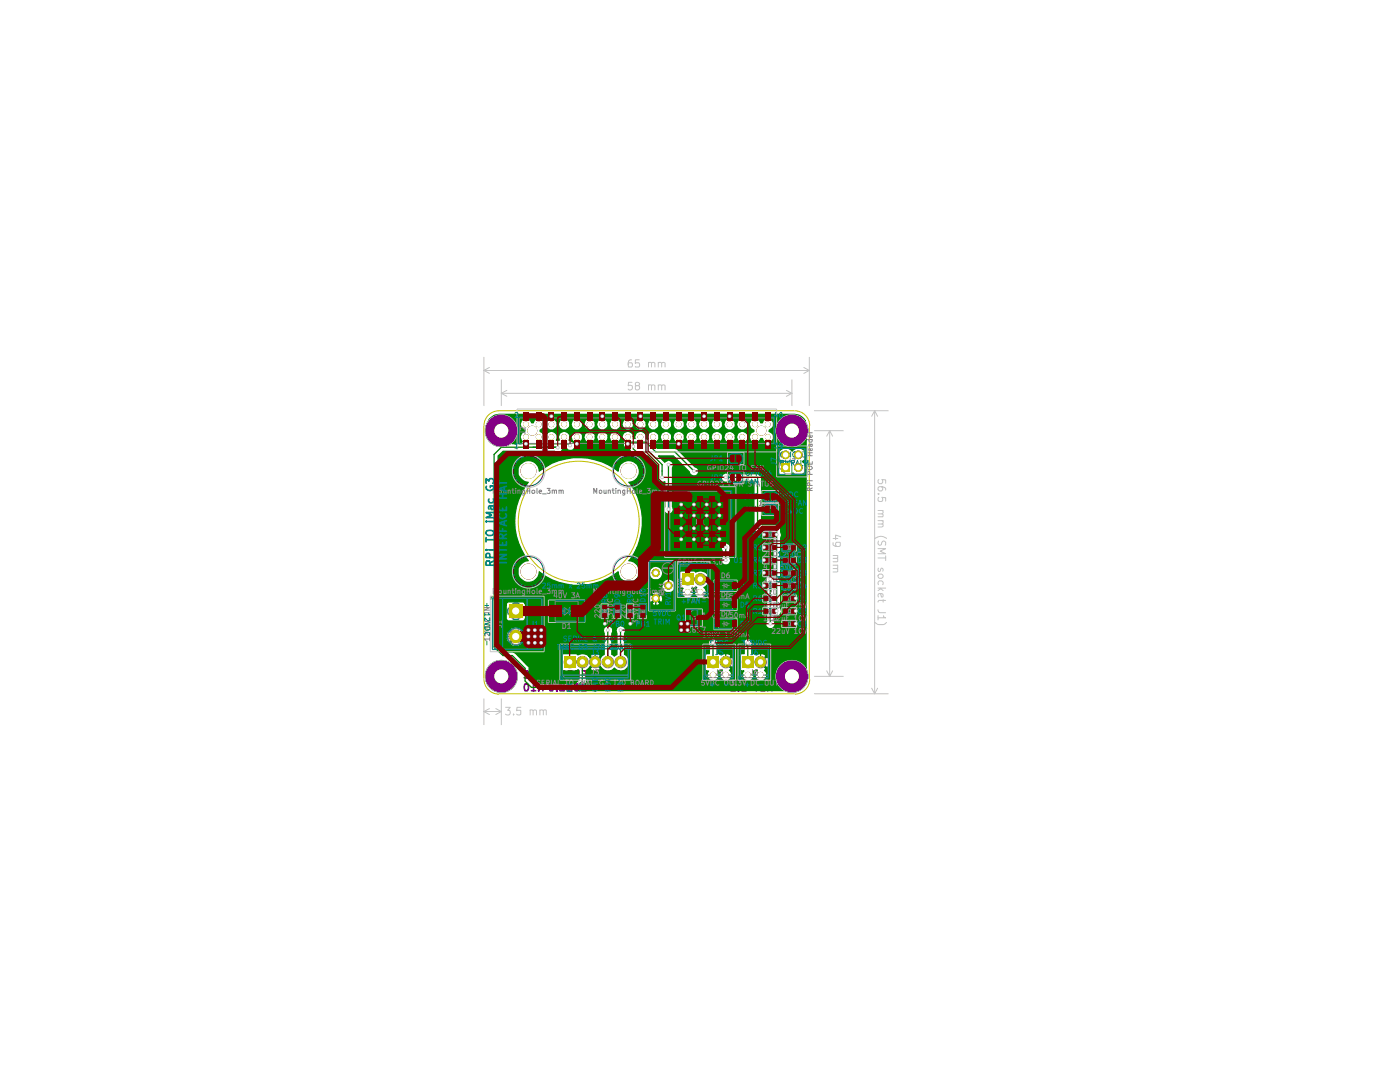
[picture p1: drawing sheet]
<svg xmlns="http://www.w3.org/2000/svg" width="279mm" height="216mm" viewBox="0 0 279 216" stroke-linecap="round" stroke-linejoin="round" font-family="sans-serif">
<g fill="none" stroke="#000084" stroke-width=".2">
<circle cx="100" cy="85.9" r="3.2"/>
<circle cx="100" cy="85.9" r="1.4"/>
<circle cx="158" cy="85.9" r="3.2"/>
<circle cx="158" cy="85.9" r="1.4"/>
<circle cx="100" cy="135" r="3.2"/>
<circle cx="100" cy="135" r="1.4"/>
<circle cx="158" cy="135" r="3.2"/>
<circle cx="158" cy="135" r="1.4"/>
</g>
<g fill="none" stroke="#848484" stroke-width=".2">
<circle cx="100" cy="85.9" r="3.2"/>
<circle cx="158" cy="85.9" r="3.2"/>
<circle cx="100" cy="135" r="3.2"/>
<circle cx="158" cy="135" r="3.2"/>
</g>
<g fill="none" stroke="#840084" stroke-width=".34">
<path d="M104.6 133.9h.6l.4 .6-.1 .5-.3 .3-.6-.1M104.8 136.5l.2-.1a.79 .79 0 0 1 .6 .6 .79 .79 0 0 1-.4 .8h-.4l-.2-.5zM106.1 137.8h.8M106.1 133.9v1.4l1-1.4v1.4M106.9 136.8l-.4-.4v1.4M107.5 137.8h.1M107.8 133.9v1.4M108.3 136.9v.9M108.7 136.3l.3 1.1h-.9M109.6 133.9h.6a1.12 1.12 0 0 1 0 1.4l-.7-.1v-.5h.3M109.8 136.5a.36 .36 0 0 1 .6 .2l.1 .6-.2 .5h-.5l-.2-.5zM111.1 133.9v1.4l.9-1.4v1.4"/>
<path d="M111.1 137.8h.1M112.6 136.5h-.8l-.1 .3 1 1h-1M112.7 133.9v1.4M113.8 134.6l-.5 .7M114 136.5l-.6-.1-.1 .1-.1 .3 .9 1h-.9M114.2 134.6l-.8-.1v-.6h.8v1.4M114.8 136.5l.3-.1a1.1 1.1 0 0 1 .2 1.4h-.4l-.2-.2-.1-.6zM114.9 133.9h.6v1.4h-.6M115 134.5h.5M116.2 133.9h.7v1.4h-.7M116.4 134.5h.5M116.9 136.5l-.6-.1-.2 .1-.1 .3 1 1h-1"/>
<path d="M117.6 133.9v1.4l.9-1.4v1.4M119.2 133.9v1.4M119.9 133.9h.6l.3 .6-.1 .5-.2 .3h-.6v-.6h.2M121.4 133.9v1.4l.8-1.4v1.4M122.9 133.9h.7v1.4h-.7M123.1 134.5h.5M125.9 134.6l-.5 .7M126.3 134.6l-.8-.1-.1-.1v-.5h.9v1.4M146.7 136.5h-.8v.3l.9 1h-.9M147.4 137.8h.1M148.1 137.8h.8M148.9 136.8l-.4-.4v1.4"/>
<path d="M150.4 136.4l.5 1.4 .5-1.4M151.9 136.4h.7v1.4h-.7M152.1 137.1h.5M153.7 137.2l-.5 .6M154.1 137.2l-.7-.1-.2-.2 .1-.4 .8-.1v1.4"/>
</g>
<g fill="#848400">
<path d="M136.1 114.5h2.2v2.2h-2.2z"/>
<path d="M141.2 131h2.2v2.2h-2.2z"/>
<path d="M155.9 92.5h1.7v1.6h-1.7z"/>
<path d="M156.2 90.2l.6-.3v1.7a.85 .85 0 0 1-.8-.5 .85 .85 0 0 1 .2-.9z"/>
<path d="M156.8 89.9a.85 .85 0 0 1 .8 .9 .85 .85 0 0 1-.8 .8z"/>
<path d="M158.7 92.7l.6-.2v1.7a.85 .85 0 0 1-.8-.6 .85 .85 0 0 1 .2-.9z"/>
<path d="M159.3 92.5a.85 .85 0 0 1 .9 .8 .85 .85 0 0 1-.9 .9z"/>
<path d="M158.7 90.2l.6-.3v1.7a.85 .85 0 0 1-.8-.5 .85 .85 0 0 1 .2-.9z"/>
<path d="M159.3 89.9a.85 .85 0 0 1 .9 .9 .85 .85 0 0 1-.9 .8z"/>
<path d="M101.6 120.6h2.6v2.7h-2.6z"/>
<path d="M112.6 131h2.2v2.2h-2.2z"/>
<path d="M148.1 131h2.2v2.2h-2.2z"/>
<circle cx="137.2" cy="118.1" r=".55"/>
<circle cx="133.4" cy="116.8" r=".8"/>
<circle cx="130.9" cy="119.4" r=".8"/>
<circle cx="116.2" cy="132.1" r="1.14"/>
<circle cx="118.8" cy="132.1" r="1.14"/>
<circle cx="121.3" cy="132.1" r="1.14"/>
<circle cx="123.8" cy="132.1" r="1.14"/>
<circle cx="139.8" cy="115.6" r="1.14"/>
<circle cx="139.8" cy="118.1" r=".55"/>
<circle cx="151.9" cy="85.9" r=".97"/>
<circle cx="148.1" cy="87.2" r=".55"/>
<circle cx="148.1" cy="84.7" r=".55"/>
<circle cx="150.7" cy="84.7" r=".55"/>
<circle cx="153.2" cy="84.7" r=".55"/>
<circle cx="140.5" cy="87.2" r=".55"/>
<circle cx="143.1" cy="87.2" r=".55"/>
<circle cx="145.6" cy="87.2" r=".55"/>
<circle cx="140.5" cy="84.7" r=".55"/>
<circle cx="143.1" cy="84.7" r=".55"/>
<circle cx="145.6" cy="84.7" r=".55"/>
<circle cx="135.4" cy="87.2" r=".55"/>
<circle cx="138" cy="87.2" r=".55"/>
<circle cx="135.4" cy="84.7" r=".55"/>
<circle cx="138" cy="84.7" r=".55"/>
<circle cx="158" cy="85.9" r="3.2"/>
<circle cx="150.7" cy="87.2" r=".55"/>
<circle cx="153.2" cy="87.2" r=".55"/>
<circle cx="105.5" cy="114" r="1.57"/>
<circle cx="100" cy="135" r="3.2"/>
<circle cx="102.9" cy="127" r="1.31"/>
<circle cx="158" cy="135" r="3.2"/>
<circle cx="142.3" cy="134.6" r=".55"/>
<circle cx="144.8" cy="132.1" r="1.14"/>
<circle cx="144.8" cy="134.6" r=".55"/>
<circle cx="151.8" cy="134.6" r=".55"/>
<circle cx="151.8" cy="132.1" r="1.14"/>
<circle cx="149.2" cy="134.6" r=".55"/>
<circle cx="125.4" cy="114" r="1.57"/>
<circle cx="125.4" cy="94" r="1.57"/>
<circle cx="105.5" cy="94" r="1.57"/>
<circle cx="125.3" cy="87.2" r=".55"/>
<circle cx="127.8" cy="87.2" r=".55"/>
<circle cx="130.4" cy="87.2" r=".55"/>
<circle cx="132.9" cy="87.2" r=".55"/>
<circle cx="130.9" cy="114.3" r=".8"/>
<circle cx="100" cy="85.9" r="3.2"/>
<circle cx="106.2" cy="85.9" r=".97"/>
<circle cx="105" cy="87.2" r=".55"/>
<circle cx="107.5" cy="87.2" r=".55"/>
<circle cx="110" cy="87.2" r=".55"/>
<circle cx="105" cy="84.7" r=".55"/>
<circle cx="107.5" cy="84.7" r=".55"/>
<circle cx="110" cy="84.7" r=".55"/>
<circle cx="117.7" cy="87.2" r=".55"/>
<circle cx="120.2" cy="87.2" r=".55"/>
<circle cx="122.7" cy="87.2" r=".55"/>
<circle cx="117.7" cy="84.7" r=".55"/>
<circle cx="120.2" cy="84.7" r=".55"/>
<circle cx="112.6" cy="87.2" r=".55"/>
<circle cx="115.1" cy="87.2" r=".55"/>
<circle cx="112.6" cy="84.7" r=".55"/>
<circle cx="115.1" cy="84.7" r=".55"/>
<circle cx="122.7" cy="84.7" r=".55"/>
<circle cx="125.3" cy="84.7" r=".55"/>
<circle cx="127.8" cy="84.7" r=".55"/>
<circle cx="130.4" cy="84.7" r=".55"/>
<circle cx="132.9" cy="84.7" r=".55"/>
</g>
<g fill="none" stroke="#008400" stroke-width=".25">
<path d="M100 89.2l-1.4 1.5v38.4M101.7 90.2l-1.3 1.2v35l.6 .6h1.9M120.2 83.1l34.4-.1v5.6h-19.2l.5 .3 4.1 4.1v7.7M129.6 90.2l1.3 1.2M130.9 90.2h3.8M144.8 95.2h6.4v10.2h3.8v16.5M130.9 119.4v5.1M135.9 102.9h7.7M135.9 105.4h7.7M138.5 100.7v6.9M141 100.7v6.9M143.6 107.6v-6.9h-7.7v6.9h16.2l.4 .3"/>
<path d="M144.8 109.2v2.6M152.5 106.7v20.3M153.7 115.6v8.9M158.8 119.4v7.6h-26.7M137.2 125.7v1.3M142.3 128.3v3.8M144.8 127v5.1M149.2 128.3v3.8M151.8 127v5.1"/>
</g>
<path d="M97.6 83.7a2.84 2.84 0 0 1 2-1l59.4 .1a2.28 2.28 0 0 1 1.7 1.3 3.2 3.2 0 0 0-4.8-.5 3.2 3.2 0 0 0 .2 4.9 3.2 3.2 0 0 0 4.8-.9v45.8l-.3-.4a3.2 3.2 0 0 0-5-.1 3.2 3.2 0 0 0 .9 4.9h-41l1.5-1.5v-2.6l.5-.3h.3a.99 .99 0 0 0 1.1 .5l.8-.3 .1-.2-1-1-1 1h-.3l1.1-1.3h.4l1.6 1.6a1.67 1.67 0 0 0 2-.4 1.74 1.74 0 0 0 2.4 .1 1.74 1.74 0 0 0 .2-2.4h15.4v2.4l.1 .3 .7 .2-.2 .3a1.22 1.22 0 0 0 .5 1.6 1.24 1.24 0 0 0 1.5-.4 1.24 1.24 0 0 0 .1-1.5l.6-.3 .2 .1a1.21 1.21 0 0 0 .3 2.1 1.21 1.21 0 0 0 1.7-1.2l-.3-.7-.2-.2 .2-.1 .1-.2-1.3-1.2 .4-.1 1.1 1.1a1.3 1.3 0 0 0 0-2.1l-1.1 1h-.4l1.2-1.1h1.8v2.5l.2 .3 .6 .1a1.2 1.2 0 0 0 .1 1.6 1.2 1.2 0 0 0 1.6 0 1.2 1.2 0 0 0 .1-1.6h.4l.3-.3 .2 .1a1.17 1.17 0 0 0-.2 1.7 1.17 1.17 0 0 0 1.7 .1 1.17 1.17 0 0 0 0-1.7l.2-.4-1.1-1.3h.3l1 1.1 .3-.1a1.54 1.54 0 0 0 0-1.8l-.3-.2-1 1h-.3l1.1-1.2v-.2l-.4-.2a1.61 1.61 0 0 0-1.5 .2l-.3-.3h-.6v-1.5l.2-.2v-.6l-.2-.4-.6-.3a1.01 1.01 0 0 0-.9 1.5v1.5h-.6l-.3 .6h-1.8v-.3a1.73 1.73 0 0 0-1.9 0l-.2-.3h-.6l.1-1.6a1.06 1.06 0 0 0-.9-1.4l-.7 .3-.2 .4v.6l.2 .2v1.5h-.6l-.4 .3v.3h-15.4l-.6-.4v-4.2l.2-.3v-.6l-.2-.3-.8-.4-.5 .3-.3 .6 .1 .7v4.2l-.5 .3-.5-.3v-4.2l.2-.3v-.6l-.2-.3-.7-.4a1.01 1.01 0 0 0-.8 1.6v4.2l-.4 .2-1.2 1.3h-.4l-.8-.7-.3-.5h.3l1 1.1 1-1.1-.1-.2-.3-.2a1.24 1.24 0 0 0-1.6 .4l-.4-.1a1.85 1.85 0 0 0-2.1-.1l-.2-.3h-2.7l-.4 .5v2.6l.3 .3 2.7 .1 .3-.3 .2 .1v2l-.8 .7h-8.3l-.8-.7-.1-2.7-2.9-2.8-1.9-.1-1.3-1.3v-.4h2.4l.1 .3 .4 .2a1.44 1.44 0 0 0 1.9-.5l-1.2-1.1-1.2 1.1h-2.4v-1.3h1.6l.3 1 .3 .1 1.2-1.2h.3l1.2 1.2a1.29 1.29 0 0 0 .5-1.6l-.2-.6-.3-.1-1.2 1.1h-.3l-1.2-1.1a.96 .96 0 0 0-.6 1.2h-1.6v-1.4h2.4l1.2 1.2 1.2-1.2-.6-.4-.7-.2-.8 .2-.3 .4h-2.4v-5h1.6v2.9l.3 .2 3.2 .1 .4-.6-.1-2.9h25.3l.3 .4 1.1-.1 .2-.3-.8-.7-.8 .7h-25.4l-.2-.3h-3.1l-.4 .3v.3h-1.6v-1.2h30.2a.49 .49 0 0 0 .4 .7l.7-.8h.4l.7 .8h.3a1.61 1.61 0 0 0 0-1.5h-.3l-.7 .7h-.4l-.7-.7h-.3l-.1 .8h-30.2v-1h30.7l.8 .8 .8-.8a.92 .92 0 0 0-1.5-.2l-.1 .2h-30.7v-14.4h3.3a13 13 0 0 0 2.7 7.8l-.6 .1a2.17 2.17 0 0 0-1.3 2.9 2.17 2.17 0 0 0 3 1.1l.9-.9 .2-1a11.9 11.9 0 0 0 6.8 2.7h17.7v.5a1.38 1.38 0 0 0 2 .8 1.38 1.38 0 0 0 .4-2.1 1.38 1.38 0 0 0-2.2 0l-.2 .8h-16a12.4 12.4 0 0 0 7.3-2.7 2.12 2.12 0 0 0 2 2.1 2.12 2.12 0 0 0 2.2-1.9h2v.5a1.39 1.39 0 0 0 1.4 .9 1.39 1.39 0 0 0 1.3-1.2h3.2v2.4l.2 .3 .6 .2-.1 .2a1.22 1.22 0 0 0 .5 1.7 1.24 1.24 0 0 0 1.5-.4 1.24 1.24 0 0 0 0-1.5l.7-.3 .1 .1-.3 .4a1.22 1.22 0 0 0 .5 1.7 1.24 1.24 0 0 0 1.5-.4 1.24 1.24 0 0 0 0-1.5l-.2-.2a1.73 1.73 0 0 0 .8-2.4 1.73 1.73 0 0 0-2.4-.6l-.3-.3h-2.7l-.3 .3-.1 .3h-3.2v-.2a1.36 1.36 0 0 0-1.4-1.3 1.36 1.36 0 0 0-1.3 1.3h-2v-.5a2.17 2.17 0 0 0-2.1-1.9l1.1-1.5 .6-1.2h16.7v.4l.2 .3v1.4l-.2 .2 .1 .8a.95 .95 0 0 0 1.4 .4 .95 .95 0 0 0 .2-1.4l.1-1.5a1.06 1.06 0 0 0-.9-1.5l-.7 .4-.2 .5h-16.7a12.8 12.8 0 0 0-1.7-13 2.16 2.16 0 0 0 2.2-2.1 2.16 2.16 0 0 0-2.1-2.2 2.16 2.16 0 0 0-2.2 2.1 12.8 12.8 0 0 0-15.8 0 2.16 2.16 0 0 0-1.8-2.1 2.16 2.16 0 0 0-2.4 1.5v1.3l.2 .3 .9 1 .9 .2a13 13 0 0 0-2.7 7.9h-3.3v-13.1l1-1h10.3a.93 .93 0 0 0 1 .3 .93 .93 0 0 0 .6-.9h.7l.6 .5h.5l.6-.4v-.8l-.1-.4-1-.5 .1-.7h.3a1.15 1.15 0 0 0 1.1 1.2 1.15 1.15 0 0 0 1.2-1.2h.2v.2a1.15 1.15 0 0 0 1.3 1.1 1.15 1.15 0 0 0 1-1.3h.3v.2a1.15 1.15 0 0 0 1.2 1.1 1.15 1.15 0 0 0 1-1.3h.3v.2a1.15 1.15 0 0 0 1.3 1.1 1.15 1.15 0 0 0 1-1.3h.2l.2 .7 .3 .3a.9 .9 0 0 0 0 1 .9 .9 0 0 0 1 .4l.2 .6 1 .9h2.5l2.1 2.1v1.7l-.2 .2v.6a1.03 1.03 0 0 0 1.5 .5v5l-.2 .3v.6a.95 .95 0 0 0 1.3 .5 .95 .95 0 0 0 .4-1.4v-5.9h9.7a.9 .9 0 0 0 .5 .9 .9 .9 0 0 0 1 0h5.1v9.7l.4 .4h3.3l.1 8.7-.6-.2-.7 .3-.2 .4v.6l.2 .2-.1 8.8a.95 .95 0 0 0 1.4 .4 .95 .95 0 0 0 .2-1.4l.1-1.2a.91 .91 0 0 0 1.2-.2 .91 .91 0 0 0 0-1.1v-14.2l.2-.4-.2-1.5-.3-.5-.5-.2h-3v-9.5l-.2-.3-.6-.4h-5.9l-.5-.1-.7 .3-.2 .5h-9.7l.1-1.9a1.06 1.06 0 0 0-.9-1.5l-.7 .4-1.3-1.2h3l3.2 3.2v.2a.96 .96 0 0 0 1.6 .4 .96 .96 0 0 0-.4-1.6l-.8-.7h17.3v1.7l.3 .6 2.2 .1 .5-.5a1.5 1.5 0 0 0 2.3-.1 1.5 1.5 0 0 0-.5-2.2 1.49 1.49 0 0 0 .3-2.4 1.49 1.49 0 0 0-2.3 .3 1.49 1.49 0 0 0-2.2-.4 1.49 1.49 0 0 0-.1 2.3l-.4 .3-.1 .3h-17.3l-2.9-2.9-.4-.1h-3.5l-1.2-1.2h.1a1.2 1.2 0 0 0 1.4-1.2h.3v.2a1.15 1.15 0 0 0 1.2 1.1 1.15 1.15 0 0 0 1-1.3h.3v.2a1.15 1.15 0 0 0 1.3 1.1 1.15 1.15 0 0 0 1-1.3h.2v.2a1.15 1.15 0 0 0 1.3 1.1 1.15 1.15 0 0 0 1-1.3h.3v.2a1.15 1.15 0 0 0 1.2 1.1 1.15 1.15 0 0 0 1.1-1.3h.2v.2a1.15 1.15 0 0 0 1.3 1.1 1.15 1.15 0 0 0 1-1.3h.3v.2a1.15 1.15 0 0 0 1.2 1.1 1.15 1.15 0 0 0 1-1.3h.3v.2a1.17 1.17 0 0 0 1.6 1 1.17 1.17 0 0 0 .5-1.8 1.17 1.17 0 0 0-1.9 0l-.2 .6h-.3a1.15 1.15 0 0 0-1.1-1 1.15 1.15 0 0 0-1.1 1h-.3v-.2a1.18 1.18 0 0 0-1.2-.8 1.18 1.18 0 0 0-1.1 1h-.2v-.2a1.18 1.18 0 0 0-1.2-.8 1.18 1.18 0 0 0-1.1 1h-.3v-.2a1.18 1.18 0 0 0-1.2-.8 1.18 1.18 0 0 0-1.1 1h-.2v-.2a1.18 1.18 0 0 0-1.2-.8 1.18 1.18 0 0 0-1.1 1h-.3v-.2a1.18 1.18 0 0 0-1.2-.8 1.18 1.18 0 0 0-1 1h-.3v-.2a1.17 1.17 0 0 0-1.5-.8 1.17 1.17 0 0 0-.7 1.6l-.3-.2v-.6a1.14 1.14 0 0 0-1.4-.8 1.14 1.14 0 0 0-.8 1.4h-.4v-.6a1.18 1.18 0 0 0-1.2-.8 1.18 1.18 0 0 0-1.1 1h-.2v-.2a1.18 1.18 0 0 0-1.2-.8 1.18 1.18 0 0 0-1.1 1h-.3v-.2a1.18 1.18 0 0 0-1.2-.8 1.18 1.18 0 0 0-1 1h-.3v-.2a1.18 1.18 0 0 0-1.2-.8 1.18 1.18 0 0 0-1.1 1h-.2v-.2a1.18 1.18 0 0 0-1.2-.8 1.18 1.18 0 0 0-1.1 1h-.3v-.2a1.17 1.17 0 0 0-1.6-.7 1.17 1.17 0 0 0-.5 1.6h-.6h.1a1.16 1.16 0 0 0-1.1-1.7 1.16 1.16 0 0 0-.9 1.7h-.6h.1a1.18 1.18 0 0 0-.8-1.7v-.3l.8-.6v-.7h.3a1.15 1.15 0 0 0 1.1 1.3 1.15 1.15 0 0 0 1.2-1.3h.2v.3a1.15 1.15 0 0 0 1.3 1 1.15 1.15 0 0 0 1-1.3h.3v.3a1.15 1.15 0 0 0 1.2 1 1.15 1.15 0 0 0 1.1-1.3h.2v.3a1.15 1.15 0 0 0 1.3 1 1.15 1.15 0 0 0 1-1.3h.3v.3a1.15 1.15 0 0 0 1.2 1 1.15 1.15 0 0 0 1-1.3h.3v.3a1.15 1.15 0 0 0 1.3 1 1.15 1.15 0 0 0 1-1.3h.2v.3a1.15 1.15 0 0 0 1.3 1 1.15 1.15 0 0 0 1-1.3h.3v.3a1.15 1.15 0 0 0 1.2 1 1.15 1.15 0 0 0 1.1-1.3h.2v.3a1.15 1.15 0 0 0 1.3 1 1.15 1.15 0 0 0 1-1.3h.3v.3a1.15 1.15 0 0 0 1.2 1 1.15 1.15 0 0 0 1-1.3h.3v.3a1.15 1.15 0 0 0 1.3 1 1.15 1.15 0 0 0 1-1.3h.2v.3a1.15 1.15 0 0 0 1.3 1 1.15 1.15 0 0 0 1-1.3h.3v.3a1.15 1.15 0 0 0 1.2 1 1.15 1.15 0 0 0 1.1-1.3h.2v.3a1.15 1.15 0 0 0 1.3 1 1.15 1.15 0 0 0 1-1.3h.3v.3a1.15 1.15 0 0 0 1.2 1 1.15 1.15 0 0 0 1-1.3h.3v.3a1.15 1.15 0 0 0 1.3 1 1.15 1.15 0 0 0 1-1.3h.2l.3 .9 .7 .4v.3a1.18 1.18 0 0 0-1 1.1 1.18 1.18 0 0 0 .9 1.1 1.37 1.37 0 0 0 1.4-.8h.4l.3 .6a1.17 1.17 0 0 0 1.8-.4 1.17 1.17 0 0 0-.8-1.6l.1-.3a1.15 1.15 0 0 0 .5-1.9 1.15 1.15 0 0 0-1.9 .5h-.4l-.1-.3a1.21 1.21 0 0 0-1.2-.5 1.21 1.21 0 0 0-1 .9h-.2v-.1a1.18 1.18 0 0 0-1.2-.8 1.18 1.18 0 0 0-1.1 .9h-.3v-.1a1.18 1.18 0 0 0-1.2-.8 1.18 1.18 0 0 0-1 .9h-.3v-.1a1.18 1.18 0 0 0-1.2-.8 1.18 1.18 0 0 0-1.1 .9h-.2v-.1a1.18 1.18 0 0 0-1.2-.8 1.18 1.18 0 0 0-1.1 .9h-.3v-.1a1.18 1.18 0 0 0-1.2-.8 1.18 1.18 0 0 0-1.1 .9h-.2v-.1a1.18 1.18 0 0 0-1.2-.8 1.18 1.18 0 0 0-1.1 .9h-.3v-.1a1.18 1.18 0 0 0-1.2-.8 1.18 1.18 0 0 0-1 .9h-.3v-.1a1.18 1.18 0 0 0-1.2-.8 1.18 1.18 0 0 0-1.1 .9h-.2v-.1a1.18 1.18 0 0 0-1.2-.8 1.18 1.18 0 0 0-1.1 .9h-.3v-.1a1.18 1.18 0 0 0-1.2-.8 1.18 1.18 0 0 0-1.1 .9h-.2v-.1a1.18 1.18 0 0 0-1.2-.8 1.18 1.18 0 0 0-1.1 .9h-.3v-.1a1.18 1.18 0 0 0-1.2-.8 1.18 1.18 0 0 0-1 .9h-.3v-.1a1.18 1.18 0 0 0-1.2-.8 1.18 1.18 0 0 0-1.1 .9h-.2v-.1a1.18 1.18 0 0 0-1.2-.8 1.18 1.18 0 0 0-1.1 .9h-.3v-.1a1.18 1.18 0 0 0-1.2-.8 1.18 1.18 0 0 0-1.1 .9h-.2v-.1a1.18 1.18 0 0 0-1.2-.8 1.18 1.18 0 0 0-1.1 .9h-.3v-.1a1.13 1.13 0 0 0-1.1-.9 1.13 1.13 0 0 0-1.1 .9h-.3l-.1-.3a1.16 1.16 0 0 0-1.9-.1 1.16 1.16 0 0 0 .6 1.8v.3a1.14 1.14 0 0 0-.5 2l-.1 .4h-2a3.2 3.2 0 0 0 .2-4.9 3.2 3.2 0 0 0-4.8 .5z" fill="#008400"/>
<g fill="none" stroke="#008400" stroke-width=".25">
<path d="M97.6 83.7a2.84 2.84 0 0 1 2-1l59.4 .1a2.28 2.28 0 0 1 1.7 1.3 3.2 3.2 0 0 0-4.8-.5 3.2 3.2 0 0 0 .2 4.9 3.2 3.2 0 0 0 4.8-.9v45.8l-.3-.4a3.2 3.2 0 0 0-5-.1 3.2 3.2 0 0 0 .9 4.9h-41l1.5-1.5v-2.6l.5-.3h.3a.99 .99 0 0 0 1.1 .5l.8-.3 .1-.2-1-1-1 1h-.3l1.1-1.3h.4l1.6 1.6a1.67 1.67 0 0 0 2-.4 1.74 1.74 0 0 0 2.4 .1 1.74 1.74 0 0 0 .2-2.4h15.4v2.4l.1 .3 .7 .2-.2 .3a1.22 1.22 0 0 0 .5 1.6 1.24 1.24 0 0 0 1.5-.4 1.24 1.24 0 0 0 .1-1.5l.6-.3 .2 .1a1.21 1.21 0 0 0 .3 2.1 1.21 1.21 0 0 0 1.7-1.2l-.3-.7-.2-.2 .2-.1 .1-.2-1.3-1.2 .4-.1 1.1 1.1a1.3 1.3 0 0 0 0-2.1l-1.1 1h-.4l1.2-1.1h1.8v2.5l.2 .3 .6 .1a1.2 1.2 0 0 0 .1 1.6 1.2 1.2 0 0 0 1.6 0 1.2 1.2 0 0 0 .1-1.6h.4l.3-.3 .2 .1a1.17 1.17 0 0 0-.2 1.7 1.17 1.17 0 0 0 1.7 .1 1.17 1.17 0 0 0 0-1.7l.2-.4-1.1-1.3h.3l1 1.1 .3-.1a1.54 1.54 0 0 0 0-1.8l-.3-.2-1 1h-.3l1.1-1.2v-.2l-.4-.2a1.61 1.61 0 0 0-1.5 .2l-.3-.3h-.6v-1.5l.2-.2v-.6l-.2-.4-.6-.3a1.01 1.01 0 0 0-.9 1.5v1.5h-.6l-.3 .6h-1.8v-.3a1.73 1.73 0 0 0-1.9 0l-.2-.3h-.6l.1-1.6a1.06 1.06 0 0 0-.9-1.4l-.7 .3-.2 .4v.6l.2 .2v1.5h-.6l-.4 .3v.3h-15.4l-.6-.4v-4.2l.2-.3v-.6l-.2-.3-.8-.4a.97 .97 0 0 0-.7 1.6v4.2l-.5 .3-.5-.3v-4.2l.2-.3v-.6l-.2-.3-.7-.4a1.01 1.01 0 0 0-.8 1.6v4.2l-.4 .2-1.2 1.3h-.4l-.8-.7-.3-.5h.3l1 1.1 1-1.1-.1-.2-.3-.2a1.24 1.24 0 0 0-1.6 .4l-.4-.1a1.85 1.85 0 0 0-2.1-.1l-.2-.3h-2.7l-.4 .5v2.6l.3 .3 2.7 .1 .3-.3 .2 .1v2l-.8 .7h-8.3l-.8-.7-.1-2.7-2.9-2.8-1.9-.1-1.3-1.3v-.4h2.4l.1 .3 .4 .2a1.44 1.44 0 0 0 1.9-.5l-1.2-1.1-1.2 1.1h-2.4v-1.3h1.6l.3 1 .3 .1 1.2-1.2h.3l1.2 1.2a1.29 1.29 0 0 0 .5-1.6l-.2-.6-.3-.1-1.2 1.1h-.3l-1.2-1.1a.96 .96 0 0 0-.6 1.2h-1.6v-1.4h2.4l1.2 1.2 1.2-1.2-.6-.4-.7-.2-.8 .2-.3 .4h-2.4v-5h1.6v2.9l.3 .2 3.2 .1 .4-.6-.1-2.9h25.3l.3 .4 1.1-.1 .2-.3-.8-.7-.8 .7h-25.4l-.2-.3h-3.1l-.4 .3v.3h-1.6v-1.2h30.2a.49 .49 0 0 0 .4 .7l.7-.8h.4l.7 .8h.3a1.61 1.61 0 0 0 0-1.5h-.3l-.7 .7h-.4l-.7-.7h-.3l-.1 .8h-30.2v-1h30.7l.8 .8 .8-.8a.92 .92 0 0 0-1.5-.2l-.1 .2h-30.7v-14.4h3.3a13 13 0 0 0 2.7 7.8l-.6 .1a2.17 2.17 0 0 0-1.3 2.9 2.17 2.17 0 0 0 3 1.1l.9-.9 .2-1a11.9 11.9 0 0 0 6.8 2.7h17.7v.5a1.38 1.38 0 0 0 2 .8 1.38 1.38 0 0 0 .4-2.1 1.38 1.38 0 0 0-2.2 0l-.2 .8h-16a12.4 12.4 0 0 0 7.3-2.7 2.12 2.12 0 0 0 2 2.1 2.12 2.12 0 0 0 2.2-1.9h2v.5a1.39 1.39 0 0 0 1.4 .9 1.39 1.39 0 0 0 1.3-1.2h3.2v2.4l.2 .3 .6 .2-.1 .2a1.22 1.22 0 0 0 .5 1.7 1.24 1.24 0 0 0 1.5-.4 1.24 1.24 0 0 0 0-1.5l.7-.3 .1 .1-.3 .4a1.22 1.22 0 0 0 .5 1.7 1.24 1.24 0 0 0 1.5-.4 1.24 1.24 0 0 0 0-1.5l-.2-.2a1.73 1.73 0 0 0 .8-2.4 1.73 1.73 0 0 0-2.4-.6l-.3-.3h-2.7l-.3 .3-.1 .3h-3.2v-.2a1.36 1.36 0 0 0-1.4-1.3 1.36 1.36 0 0 0-1.3 1.3h-2v-.5a2.17 2.17 0 0 0-2.1-1.9l1.1-1.5 .6-1.2h16.7v.4l.2 .3v1.4l-.2 .2 .1 .8a.95 .95 0 0 0 1.4 .4 .95 .95 0 0 0 .2-1.4l.1-1.5a1.06 1.06 0 0 0-.9-1.5l-.7 .4-.2 .5h-16.7a12.8 12.8 0 0 0-1.7-13 2.16 2.16 0 0 0 2.2-2.1 2.16 2.16 0 0 0-2.1-2.2 2.16 2.16 0 0 0-2.2 2.1 12.8 12.8 0 0 0-15.8 0 2.16 2.16 0 0 0-1.8-2.1 2.16 2.16 0 0 0-2.4 1.5v1.3l.2 .3 .9 1 .9 .2a13 13 0 0 0-2.7 7.9h-3.3v-13.1l1-1h10.3a.93 .93 0 0 0 1 .3 .93 .93 0 0 0 .6-.9h.7l.6 .5h.5l.6-.4v-.8l-.1-.4-1-.5 .1-.7h.3a1.15 1.15 0 0 0 1.1 1.2 1.15 1.15 0 0 0 1.2-1.2h.2v.2a1.15 1.15 0 0 0 1.3 1.1 1.15 1.15 0 0 0 1-1.3h.3v.2a1.15 1.15 0 0 0 1.2 1.1 1.15 1.15 0 0 0 1-1.3h.3v.2a1.15 1.15 0 0 0 1.3 1.1 1.15 1.15 0 0 0 1-1.3h.2l.2 .7 .3 .3a.9 .9 0 0 0 0 1 .9 .9 0 0 0 1 .4l.2 .6 1 .9h2.5l2.1 2.1v1.7l-.2 .2v.6a1.03 1.03 0 0 0 1.5 .5v5l-.2 .3v.6a.95 .95 0 0 0 1.3 .5 .95 .95 0 0 0 .4-1.4v-5.9h9.7a.9 .9 0 0 0 .5 .9 .9 .9 0 0 0 1 0h5.1v9.7l.4 .4h3.3l.1 8.7-.6-.2-.7 .3-.2 .4v.6l.2 .2-.1 8.8a.95 .95 0 0 0 1.4 .4 .95 .95 0 0 0 .2-1.4l.1-1.2a.91 .91 0 0 0 1.2-.2 .91 .91 0 0 0 0-1.1v-14.2l.2-.4-.2-1.5-.3-.5-.5-.2h-3v-9.5l-.2-.3-.6-.4h-5.9l-.5-.1-.7 .3-.2 .5h-9.7l.1-1.9a1.06 1.06 0 0 0-.9-1.5l-.7 .4-1.3-1.2h3l3.2 3.2v.2a.96 .96 0 0 0 1.6 .4 .96 .96 0 0 0-.4-1.6l-.8-.7h17.3v1.7l.3 .6 2.2 .1 .5-.5a1.5 1.5 0 0 0 2.3-.1 1.5 1.5 0 0 0-.5-2.2 1.49 1.49 0 0 0 .3-2.4 1.49 1.49 0 0 0-2.3 .3 1.49 1.49 0 0 0-2.2-.4 1.49 1.49 0 0 0-.1 2.3l-.4 .3-.1 .3h-17.3l-2.9-2.9-.4-.1h-3.5l-1.2-1.2h.1a1.2 1.2 0 0 0 1.4-1.2h.3v.2a1.15 1.15 0 0 0 1.2 1.1 1.15 1.15 0 0 0 1-1.3h.3v.2a1.15 1.15 0 0 0 1.3 1.1 1.15 1.15 0 0 0 1-1.3h.2v.2a1.15 1.15 0 0 0 1.3 1.1 1.15 1.15 0 0 0 1-1.3h.3v.2a1.15 1.15 0 0 0 1.2 1.1 1.15 1.15 0 0 0 1.1-1.3h.2v.2a1.15 1.15 0 0 0 1.3 1.1 1.15 1.15 0 0 0 1-1.3h.3v.2a1.15 1.15 0 0 0 1.2 1.1 1.15 1.15 0 0 0 1-1.3h.3v.2a1.17 1.17 0 0 0 1.6 1 1.17 1.17 0 0 0 .5-1.8 1.17 1.17 0 0 0-1.9 0l-.2 .6h-.3a1.15 1.15 0 0 0-1.1-1 1.15 1.15 0 0 0-1.1 1h-.3v-.2a1.18 1.18 0 0 0-1.2-.8 1.18 1.18 0 0 0-1.1 1h-.2v-.2a1.18 1.18 0 0 0-1.2-.8 1.18 1.18 0 0 0-1.1 1h-.3v-.2a1.18 1.18 0 0 0-1.2-.8 1.18 1.18 0 0 0-1.1 1h-.2v-.2a1.18 1.18 0 0 0-1.2-.8 1.18 1.18 0 0 0-1.1 1h-.3v-.2a1.18 1.18 0 0 0-1.2-.8 1.18 1.18 0 0 0-1 1h-.3v-.2a1.17 1.17 0 0 0-1.5-.8 1.17 1.17 0 0 0-.7 1.6l-.3-.2v-.6a1.14 1.14 0 0 0-1.4-.8 1.14 1.14 0 0 0-.8 1.4h-.4v-.6a1.18 1.18 0 0 0-1.2-.8 1.18 1.18 0 0 0-1.1 1h-.2v-.2a1.18 1.18 0 0 0-1.2-.8 1.18 1.18 0 0 0-1.1 1h-.3v-.2a1.18 1.18 0 0 0-1.2-.8 1.18 1.18 0 0 0-1 1h-.3v-.2a1.18 1.18 0 0 0-1.2-.8 1.18 1.18 0 0 0-1.1 1h-.2v-.2a1.18 1.18 0 0 0-1.2-.8 1.18 1.18 0 0 0-1.1 1h-.3v-.2a1.17 1.17 0 0 0-1.6-.7 1.17 1.17 0 0 0-.5 1.6h-.6h.1a1.16 1.16 0 0 0-1.1-1.7 1.16 1.16 0 0 0-.9 1.7h-.6h.1a1.18 1.18 0 0 0-.8-1.7v-.3l.8-.6v-.7h.3a1.15 1.15 0 0 0 1.1 1.3 1.15 1.15 0 0 0 1.2-1.3h.2v.3a1.15 1.15 0 0 0 1.3 1 1.15 1.15 0 0 0 1-1.3h.3v.3a1.15 1.15 0 0 0 1.2 1 1.15 1.15 0 0 0 1.1-1.3h.2v.3a1.15 1.15 0 0 0 1.3 1 1.15 1.15 0 0 0 1-1.3h.3v.3a1.15 1.15 0 0 0 1.2 1 1.15 1.15 0 0 0 1-1.3h.3v.3a1.15 1.15 0 0 0 1.3 1 1.15 1.15 0 0 0 1-1.3h.2v.3a1.15 1.15 0 0 0 1.3 1 1.15 1.15 0 0 0 1-1.3h.3v.3a1.15 1.15 0 0 0 1.2 1 1.15 1.15 0 0 0 1.1-1.3h.2v.3a1.15 1.15 0 0 0 1.3 1 1.15 1.15 0 0 0 1-1.3h.3v.3a1.15 1.15 0 0 0 1.2 1 1.15 1.15 0 0 0 1-1.3h.3v.3a1.15 1.15 0 0 0 1.3 1 1.15 1.15 0 0 0 1-1.3h.2v.3a1.15 1.15 0 0 0 1.3 1 1.15 1.15 0 0 0 1-1.3h.3v.3a1.15 1.15 0 0 0 1.2 1 1.15 1.15 0 0 0 1.1-1.3h.2v.3a1.15 1.15 0 0 0 1.3 1 1.15 1.15 0 0 0 1-1.3h.3v.3a1.15 1.15 0 0 0 1.2 1 1.15 1.15 0 0 0 1-1.3h.3v.3a1.15 1.15 0 0 0 1.3 1 1.15 1.15 0 0 0 1-1.3h.2l.3 .9 .7 .4v.3a1.18 1.18 0 0 0-1 1.1 1.18 1.18 0 0 0 .9 1.1 1.37 1.37 0 0 0 1.4-.8h.4l.3 .6a1.17 1.17 0 0 0 1.8-.4 1.17 1.17 0 0 0-.8-1.6l.1-.3a1.15 1.15 0 0 0 .5-1.9 1.15 1.15 0 0 0-1.9 .5h-.4l-.1-.3a1.21 1.21 0 0 0-1.2-.5 1.21 1.21 0 0 0-1 .9h-.2v-.1a1.18 1.18 0 0 0-1.2-.8 1.18 1.18 0 0 0-1.1 .9h-.3v-.1a1.18 1.18 0 0 0-1.2-.8 1.18 1.18 0 0 0-1 .9h-.3v-.1a1.18 1.18 0 0 0-1.2-.8 1.18 1.18 0 0 0-1.1 .9h-.2v-.1a1.18 1.18 0 0 0-1.2-.8 1.18 1.18 0 0 0-1.1 .9h-.3v-.1a1.18 1.18 0 0 0-1.2-.8 1.18 1.18 0 0 0-1.1 .9h-.2v-.1a1.18 1.18 0 0 0-1.2-.8 1.18 1.18 0 0 0-1.1 .9h-.3v-.1a1.18 1.18 0 0 0-1.2-.8 1.18 1.18 0 0 0-1 .9h-.3v-.1a1.18 1.18 0 0 0-1.2-.8 1.18 1.18 0 0 0-1.1 .9h-.2v-.1a1.18 1.18 0 0 0-1.2-.8 1.18 1.18 0 0 0-1.1 .9h-.3v-.1a1.18 1.18 0 0 0-1.2-.8 1.18 1.18 0 0 0-1.1 .9h-.2v-.1a1.18 1.18 0 0 0-1.2-.8 1.18 1.18 0 0 0-1.1 .9h-.3v-.1a1.18 1.18 0 0 0-1.2-.8 1.18 1.18 0 0 0-1 .9h-.3v-.1a1.18 1.18 0 0 0-1.2-.8 1.18 1.18 0 0 0-1.1 .9h-.2v-.1a1.18 1.18 0 0 0-1.2-.8 1.18 1.18 0 0 0-1.1 .9h-.3v-.1a1.18 1.18 0 0 0-1.2-.8 1.18 1.18 0 0 0-1.1 .9h-.2v-.1a1.18 1.18 0 0 0-1.2-.8 1.18 1.18 0 0 0-1.1 .9h-.3v-.1a1.13 1.13 0 0 0-1.1-.9 1.13 1.13 0 0 0-1.1 .9h-.3l-.1-.3a1.16 1.16 0 0 0-1.9-.1 1.16 1.16 0 0 0 .6 1.8v.3a1.14 1.14 0 0 0-.5 2l-.1 .4h-2a3.2 3.2 0 0 0 .2-4.9 3.2 3.2 0 0 0-4.8 .5zM100 89.2l11.3 .1M105 88.6h8.4l.4 .3M110 83.1h10.2M115.2 88.6l-.1 .8-.7 .8h-12.7M125.3 88.5l.2-.3h3.4l2 2M126.4 89.1v.5l.7 .6h2.5M130.9 91.4l1.2 1.3v2.5M133.4 92.7v8.9M134.7 90.2l3.8 3.8M98.6 129.1l1.8 1.7h1.8l2.6 2.5v2.6l1.3 1.3h8.8l1.3-1.3v-3.8M108 127h9.5l2.5-2.5h12.1v2.5"/>
<path d="M108 128.3h9.5l1.3 1.2v2.6M121.3 125.7v6.4M123.8 125.7v6.4"/>
</g>
<path d="M105.5 125.7v2.6h1.2v-1.3h-3.8M108 125.7v2.6" fill="none" stroke="#008400" stroke-width="2"/>
<g fill="none" stroke="#c2c200" stroke-width=".2">
<path d="M96.6 84.9v50.6M99.5 82h59.1M99.6 82a3 3 0 0 0-3 3M158.6 82a3 3 0 0 1 3 3M161.5 84.9v50.6M96.6 135.5a3 3 0 0 0 3 3M99.5 138.4h59.1M161.6 135.5a3 3 0 0 1-3 3"/>
<circle cx="115.5" cy="104.1" r="12.1"/>
</g>
<g fill="none" stroke="#000084" stroke-width=".2">
<circle cx="105.5" cy="94" r="3"/>
<circle cx="125.4" cy="94" r="3"/>
<circle cx="105.5" cy="114" r="3"/>
<circle cx="125.4" cy="114" r="3"/>
</g>
<g fill="none" stroke="#c2c2c2" stroke-width=".2">
<path d="M96.6 71.3v9.6M96.6 73.9h64.9M96.6 73.9l1.1 .6M97.7 73.3l-1.1 .6M100 75.8v5.1M100 78.5h58M100 78.5l1.1 .6M101.1 77.9l-1.1 .6M126 71.8l-.4 .1a1.28 1.28 0 0 0-.2 1.3h.6l.2-.6-.2-.2h-.6v.2M126.1 76.3h-.7v.7h.7v.6l-.2 .2h-.4l-.1-.2M127.1 77l-.3-.2 .1-.4a.48 .48 0 0 1 .7 .2l-.3 .4h-.5v.6a.45 .45 0 0 0 .7 .1 .45 .45 0 0 0-.2-.7M127.6 71.8h-.8v.7l.7-.1 .1 .2-.1 .6h-.7"/>
<path d="M129.4 77l.2-.2 .4 .1v.9M129.4 72.4h.6v.8M129.4 72.3v.9M129.4 76.8v1M130 77l.3-.2 .4 .2v.8M130 72.5l.3-.2 .4 .2v.7M131.4 77l.2-.2 .5 .2v.8M131.4 72.4l.5-.1 .2 .2v.7M131.4 72.3v.9M131.4 76.8v1M132.1 77l.2-.2 .4 .2v.8M132.1 72.5l.2-.2 .4 .2v.7"/>
<path d="M156.9 77.9l1.1 .6M158 75.8v5.1M158 78.5l-1.1 .6M160.4 73.3l1.1 .6M161.5 71.3v9.6M161.5 73.9l-1.1 .6M132.6 97.1h14.3v14.2h-14.3zM145.2 94.1h3.3v2.4h-3.3zM145.2 90.3h3.3v2.4h-3.3zM152 97.9h3.3v2.4h-3.3zM155 89h6.1v6.2h-6.1v-13.6h-51.8v8.6h51.8M162.5 85.9h5.8"/>
<path d="M162.5 82h14.8M165.6 85.9v49.1M165.6 85.9l-.6 1.1M165.6 85.9l.6 1.1M174.6 82v56.4M174.6 82l-.6 1.1M174.6 82l.5 1.1M175.2 98.6h.2M175.4 95.7l-.2 .1v.5l.3 .2h.4l.3-.2v-.5l-.2-.1 .8 .1v.6M175.4 99.2l-.2 .3 .1 .5h.8l.1-.5-.2-.3 .8 .1v.7M175.9 97.1l.3 .3v.3l-.3 .3h-.4l-.3-.3 .1-.5a1.19 1.19 0 0 1 1.5 .3v.3M97.8 119h10.8v11h-10.8z"/>
<path d="M109.4 119.7h7.3v4.5h-7.3zM129.4 111.8h5.4v10.1h-5.4zM135.2 112h6.5v7.2h-6.5zM142.5 115.7h4.6v2.3h-4.6zM142.5 119.5h4.6v2.3h-4.6zM152 100.4h3.3v2.5h-3.3zM152.2 106h3v1.4h-3zM152.2 108.5h3v1.5h-3zM152.2 111.1h3v1.4h-3zM152.2 113.6h3v1.5h-3zM152.2 116.2h3v1.4h-3zM152.2 118.7h3v1.4h-3z"/>
<path d="M156 108.5h3v1.5h-3zM156 111.1h3v1.4h-3zM156 113.6h3v1.5h-3zM156 116.2h3v1.4h-3zM156 118.7h3v1.4h-3zM166.3 108.3v.4a1.1 1.1 0 0 0 1.4 .2l-.1-.7h-.7l-.1 .5 .3 .4M166.3 107.4h.9M166.3 110.8h.9M166.3 112.8h.9M167 111.4l.2 .1v.5l-.9 .1M167 113.5h.2v.5l-.9 .1M167.1 110.8l.1 .5-.9 .1"/>
<path d="M167.1 112.8l.1 .6-.9 .1M167.8 107.1l-1-.3v.9M174.6 107.4a1.84 1.84 0 0 1 2.3 0M175.2 109.5h1.6l-1.1 .5 1.1 .5h-1.6M175.2 101.9h1M175.2 103.9h1M175.2 111.3h1.6M175.2 117.3h1.6M175.3 107.9l-.1 .6 .3 .3 .4-.2a.6 .6 0 0 1 .4-.7l.5 .3-.1 .6M175.3 113.4l-.1 .4 .2 .2h.3l.1-.5 .2-.1a.36 .36 0 0 1 .2 .6M175.3 114.7l.2-.1h.4l.3 .3-.1 .4-.6 .1a.45 .45 0 0 1-.2-.7zM175.3 116.7a.52 .52 0 0 1 .2-.8h.4l.3 .2v.6"/>
<path d="M175.7 117.3l.5 .6M175.7 118.4l.2 .7h.3v-.4l-.2-.3-.7 .1v.6M175.8 117.4l-.6 .5M176 102.5l.2 .2v.4h-1M176 104.6l.2 .1v.4l-1 .1M176.1 101.9h.1a.36 .36 0 0 1-.2 .6h-.8M176.1 103.9l.1 .2v.4l-1 .1M176.2 119.6v.5M176.8 119.8h-1.4l-.2 .3M176.8 110.9v.9M96.6 139.4v5.2M100 139.4v5.2"/>
<path d="M111.7 128.5h14.2v7.2h-14.2zM119.9 120.5h1.5v2.9h-1.5zM122.5 120.5h1.4v2.9h-1.4zM125 120.5h1.5v2.9h-1.5zM127.6 120.5h1.4v2.9h-1.4zM136.8 121.5h3.4v3.5h-3.4zM140.3 128.5h6.5v7.2h-6.5zM142.5 123.4h4.6v2.2h-4.6zM147.3 128.5h6.5v7.2h-6.5zM152.2 121.2h3v1.5h-3zM156 121.2h3v1.5h-3zM156 123.8h3v1.4h-3z"/>
<path d="M162.5 135h5.8M162.5 138.4h14.8M165 133.9l.6 1.1M166.2 133.9l-.6 1.1M174 137.3l.6 1.1M174.6 124.2l.7 .4h1l.6-.4M175.1 137.3l-.5 1.1M175.2 121.7l.2 .5 1.4 .1M175.2 122.9v.8M176.3 122.9v.1l.5 .3h-1.6M96.6 142h3.4M96.6 142l1.1 .6"/>
<path d="M97.7 141.4l-1.1 .6M98.9 141.4l1.1 .6M100 142l-1.1 .6M100.9 141.1h.9l-.5 .6 .4 .1a.6 .6 0 0 1-.1 .9h-.5l-.2-.2M102.5 142.5v.2M103.9 141.1h-.7l-.1 .7 .8-.1v.8l-.2 .2-.6-.2M105.8 141.7l.4-.1 .2 .2v.9M105.8 141.6v1.1M106.4 141.8l.3-.2 .4 .2v.9M107.8 141.7l.4-.1 .2 .2v.9M107.8 141.6v1.1M108.4 141.8l.2-.2 .4 .1v1"/>
<circle cx="100" cy="85.9" r="3.2"/>
<circle cx="105.5" cy="94" r="3.3"/>
<circle cx="125.5" cy="94" r="3.3"/>
<circle cx="158" cy="85.9" r="3.2"/>
<circle cx="105.5" cy="114.1" r="3.3"/>
<circle cx="125.5" cy="114.1" r="3.3"/>
<circle cx="100" cy="135" r="3.2"/>
<circle cx="158" cy="135" r="3.2"/>
</g>
<g fill="none" stroke="#848484" stroke-width=".2">
<path d="M98.4 98.5v-1l.4 .7 .3-.7v1M99.5 98l.3-.2 .2 .1v.5h-.4zM100.6 97.8v.6h.4M101 97.8v.7M101.4 97.9h.4v.6M101.4 97.8v.7M102.2 97.8h.4M102.3 97.5v.9l.3 .1M102.9 97.5h.1M102.9 97.8v.7M103.3 97.9h.5v.6M103.3 97.8v.7"/>
<path d="M103.7 83.4h50.8v5.1h-50.8zM103.9 86.2h.6l.3 .2v.2M104.5 88.5l.5-.7 .4 .7M104.7 97.8v.8l-.2 .2-.2-.1M104.7 97.9l-.2-.1-.3 .2 .1 .4h.4M104.8 85.3v.6l-.5-.6h-.4v.5M105.2 98h.5M105.2 97.5v1M105.7 97.5v1M106.1 98l.3-.2 .3 .1v.4l-.2 .2-.3-.1zM107.2 97.5v1M107.6 98.1l.5-.1-.2-.2-.3 .2v.3l.2 .2 .2-.1"/>
<path d="M108.3 98.6h.7M109.2 97.5h.6l-.4 .4 .4 .1v.4h-.6M110.2 97.9h.4v.6M110.2 97.8v.7M110.6 98l.2-.2 .3 .1v.6M111.6 97.9h.4v.6M111.6 97.8v.7M112 98l.2-.2 .2 .1v.6M118.5 98.5v-1l.3 .7 .3-.7v1M119.6 97.9h.4l.1 .4-.2 .2-.3-.1zM120.5 97.8v.6h.5M121 97.8v.7"/>
<path d="M121.4 97.9h.4v.6M121.4 97.8v.7M122.1 97.8h.5M122.3 97.5v.8l.3 .2M122.9 97.5h.1M122.9 97.8v.7M123.3 97.9l.4-.1 .1 .2v.5M123.3 97.8v.7M124.7 97.8v.9h-.4M124.7 97.9h-.4v.5h.4M125.2 97.5v1M125.2 98h.6"/>
<path d="M125.8 97.5v1M126.2 97.9l.3-.1 .2 .2v.3l-.2 .2-.3-.1zM127.1 97.5v.9l.2 .1M127.6 98.1l.5-.1v-.1h-.5v.5h.5M128.2 98.6h.8M129.2 97.5h.6l-.4 .4 .4 .1v.4h-.6M130.2 97.9l.3-.1 .2 .2v.5M130.2 97.8v.7M130.7 98l.1-.2 .3 .2v.5M131.5 97.9h.5v.6M131.5 97.8v.7M132 98l.1-.2 .3 .1v.6"/>
<path d="M134.7 98h11.2v12.2h-12.2v-11.1zM139.8 96.1a.46 .46 0 0 0-.6 .5 .46 .46 0 0 0 .7 .3v-.3h-.2M140.3 96.5h.5l.1-.4-.6-.1v1M141.3 96v1M141.8 92.9l-.5 .1v.7l.5 .1 .1-.4h-.3M142 96l.4 .2v.7l-.2 .1-.4-.1v-.7zM142.3 93.4l.5-.1-.1-.4h-.4v.9M142.8 96.1l.3-.1 .3 .3-.7 .7h.7M143.3 92.9v.9M143.7 96h.6l-.3 .4h.2l.1 .5-.1 .1-.5-.1M143.7 93h.6l-.1 .8-.5-.1zM144.8 93l.5-.1v.2l-.6 .7h.6"/>
<path d="M145.5 96.5h.5l.1-.3-.6-.2v1M145.9 92.8l-.2 .7h.7M146.2 93.1v.7M146.4 96l.2 1 .3-.7 .1 .7 .3-1M147.3 92.9h.6M147.6 96.5h.5l.1-.3-.1-.2h-.5v1M147.6 92.9v.9M147.9 96.5l.3 .5M148.2 93h.6l-.1 .8-.5-.1zM149.9 96.1l-.3-.1-.3 .2 .3 .3 .3 .1v.3h-.6M150 93.3h.3M150.3 96h.5"/>
<path d="M150.5 92.9h-.5v.9M150.5 96v1M150.8 93.8l.3-.9 .3 .9M150.8 93.6h.6M151 97l.4-1 .2 1M151.1 96.7h.4M151.9 96h.5M152.1 96v1M152.3 92.9v.9l-.5-.9v.9M152.5 99.9l.4-.1 .1 .2-.5 .8h.5M152.7 96v.9l.3 .1 .3-.1v-.9M153.3 99.8l.3 1 .4-1"/>
<path d="M154.3 96.1l-.4-.1-.2 .2 .2 .3 .4 .2-.2 .3-.4-.1M154.3 99.8a.52 .52 0 0 1 .6 .5 .52 .52 0 0 1-.6 .5zM155.3 84.9h.1M155.5 89.5h5.1v5.1h-3.8l-1.3-1.3zM155.7 84.9h.7M155.8 86.9v-.5h-.5v.5h1.1M155.8 85.9v-.6h-.4l-.1 .6h1.1M155.9 99.9a.47 .47 0 0 0-.7 .4 .47 .47 0 0 0 .7 .5M156.4 86.4l-.6 .3M157.7 91.5v.9l-.3 .1M158.1 91.5h.6l-.4 1M161.1 95.9h.1"/>
<path d="M161.1 92.1v.5h1v-.5M161.1 90.9h1M161.1 90.3h1M161.1 87.7h1M161.3 93h.6l.2 .5a.6 .6 0 0 1-1 0zM161.4 86.1l.2 .3M161.4 95.9h.7M161.4 86.4h.7M161.5 87.7l-.1 .3 .2 .2 .4-.1v-.4M161.6 97.9v-.4l-.4-.1-.1 .5h1M161.6 96.9v-.5h-.4l-.1 .5h1M161.6 94.7v-.6h-.3l-.2 .6h1"/>
<path d="M161.6 90.3v.6M161.6 92.3v.3M161.7 88.6l.1 .5 .3-.1-.1-.4M162 89.5v.4h-.5l-.1-.3 .3-.1 .1 .4M162 86.9l.1 .2-.2 .2h-.3l-.2-.3 .3-.2 .1 .5M162.1 88.6h-.6v.5M162.1 97.4l-.5 .2M98.3 119.9l.5-.5h9.3v10.1h-9.8zM98.4 118.4v-1l.4 .8 .3-.8v1M98.8 119.4v10.1M99.6 117.9h.4v.5h-.4zM100.3 119.4v10.1"/>
<path d="M100.6 117.8v.6h.4M101 117.8v.6M101.4 117.9h.4v.5M101.4 117.8v.6M102.2 117.8h.4M102.3 117.4v1h.3M102.9 117.4v.2M102.9 117.8v.6M103.3 117.9h.5v.5M103.3 117.8v.6M104.7 117.8v.8l-.1 .2h-.3M104.7 117.9l-.2-.1-.3 .2 .2 .4h.3"/>
<path d="M105.2 117.4v1M105.2 119.4v10.1M105.2 117.9h.5M105.7 117.4v1M107.2 117.4v1M107.6 118.1l.5-.1-.2-.2-.3 .1v.5h.4M108.3 118.5h.7M109.2 117.4h.6l-.4 .5h.4v.5h-.6M110.2 117.9h.4v.5M110.2 117.8v.6M110.6 117.9l.2-.1 .3 .1v.5M110.8 118.3l-.3 .7h.7"/>
<path d="M110.8 120h4.6v4h-4.6zM111.1 118.6v.7M111.6 117.9h.4v.5M111.6 117.8v.6M111.6 118.4l.3-.1 .2 .2-.1 .8h-.4v-.2zM112 117.9l.2-.1 .2 .1v.5M112.4 118.3l.3 1 .4-1M114.1 118.3h.6l-.3 .4h.2l.1 .2-.1 .4-.5-.1M114.9 119.3l.4-1 .3 1M115 119h.5M118.5 118.4v-1l.3 .8 .3-.8v1M119.6 117.9h.4v.5h-.4z"/>
<path d="M120.5 117.8v.6h.5M121 117.8v.6M121.4 117.9h.4v.5M121.4 119.5h-.1a.52 .52 0 0 0 .3 .6 .52 .52 0 0 0 .6-.1l-.1-.5M121.4 117.8v.6M122.1 117.8h.5M122.3 117.4v1h.3M122.9 117.4v.2M122.9 117.8v.6M123.3 117.9l.4-.1 .1 .1v.5M123.3 117.8v.6M124.7 117.8v.9l-.4 .1"/>
<path d="M124.7 117.9h-.4v.5h.4M125.2 117.4v1M125.2 117.9h.6M125.8 117.4v1M126.2 117.9h.4v.5h-.4zM126.5 119.5h-.1a.52 .52 0 0 0 .3 .6 .52 .52 0 0 0 .6-.1l-.1-.5M127.1 117.4v1h.2M127.6 118.1l.5-.1v-.1h-.5v.5h.5M128.2 118.5h.8M129.2 117.4h.6l-.4 .5h.4v.5h-.6M129.7 112.1h4.8v9.6h-4.8zM130.2 117.9l.3-.1 .2 .1v.5"/>
<path d="M130.2 117.8v.6M130.7 117.9l.1-.1 .3 .1v.5M131.5 117.2l1.1 .3-1.1 .4h.5v.5M131.5 117.8v.6M132 117.9l.1-.1 .3 .1v.5M132.1 118.7v-.5l-.3-.1-.3 .2v.4h1.1M132.2 113.4h2.1M132.6 116.6h-1.1l.4 .2M132.6 118.1l-.5 .3M132.6 116.3v.5M135.3 117.7v.5h.4v-.5l.3-.1 .2 .2-.1 .4M135.3 115.7l.7-.1 .2 .1v.3l-.8 .1-.1-.1z"/>
<path d="M135.4 112.2h.4l.1-.2-.1-.4h-.4v1M135.6 112.2l.3 .4M135.7 112.5h5.5v6.2h-5l-.5-.5zM135.7 112.9h5.5M135.7 118.2h5.5M136.2 116.5h-.9l.6 .3-.6 .4h.9M136.4 112.2h.4l.2-.2-.2-.4h-.4v1M137.3 119.7h.3M137.4 112.6v-1l.3 .8 .4-.8v1M137.8 119.2h-.5v1M137.9 114.8l-1.5 1.5M138.1 114.9l-1.6 1.5"/>
<path d="M138.1 117.1v.7l-.1 .2h-.3M138.1 120h.5M138.8 117l-.2 .7h.6M139 103.6v1h.2h.3v-1M139 111.6h-.4l-.1 .5 .5-.1v.6l-.5-.1M139 117.4v.6M139.5 112.5v.1M139.6 119.2v1l-.6-1v1M140 103.9l.3-.3v1M140 104.6h.5M140.2 111.6a.63 .63 0 0 1 .1 1 .54 .54 0 0 1-.4-.4 .54 .54 0 0 1 .3-.6zM140.3 118.7l.2-.3v1.1"/>
<path d="M140.3 119.5h.5M140.4 114.8l-1.5 1.5M140.6 114.9l-1.6 1.5M140.9 112.3h.8M141.3 118.5l.1-.1a.52 .52 0 0 1 .4 .5 .52 .52 0 0 1-.4 .6l-.2-.5zM142 111.6h.7l-.3 .4 .3 .2v.2l-.1 .2-.6-.1M142.3 118.4a.52 .52 0 0 1 .4 .5 .52 .52 0 0 1-.3 .6l-.3-.5zM143 118.4l.3 1.1 .4-1.1M143.1 112.5v.1M143.4 116h2.8v1.8h-2.8zM143.4 119.8h2.8v1.8h-2.8zM143.7 111.7l.2-.1 .2 .2-.1 .8h-.3l-.1-.2z"/>
<path d="M144.1 114.3a.59 .59 0 0 1 .5 .4 .59 .59 0 0 1-.1 .6h-.4zM144.1 118.1a.59 .59 0 0 1 .5 .4 .59 .59 0 0 1-.1 .6h-.4zM144.1 116.8h.4M144.5 116.3v1.1M144.5 116.8l.6-.3v.8zM144.8 118.7l.2-.3v1.1M144.8 119.5h.5M145.1 116.8h.5M145.5 114.3l-.3 .1a.74 .74 0 0 0-.1 .9h.4l.1-.4-.1-.2h-.4l-.1 .2M145.5 118.1h-.4l-.1 .5 .5-.1v.6l-.5-.1M146.2 118.4h-.5v.5h.5l.1 .3-.3 .3-.3-.2M146.7 118.5l.1-.1a.52 .52 0 0 1 .4 .5 .52 .52 0 0 1-.3 .6l-.3-.5z"/>
<path d="M147.6 118.9h.5v.6M147.6 118.8v.7M148.1 118.9h.4v.6M148.8 119.5l.4-1.1 .3 1.1M148.9 119.1h.5M151.5 100.1l.3-.3v1M151.5 100.8h.6M152.5 107.5l.3-.1 .2 .3-.6 .8h.6M152.5 110.1l.3-.1 .2 .2-.6 .8h.6M152.5 115.1h.4l.1 .1-.5 .9h.5M152.5 117.7l.4-.1 .1 .2-.5 .8h.5M152.5 100.4h-.5l-.1 .5 .6-.1v.5h-.6"/>
<path d="M152.7 112.4l-.2 .8h.5M152.9 100.4l.3 1 .3-1M152.9 106.3h1.6v.8h-1.6zM152.9 108.9h1.6v.7h-1.6zM152.9 111.4h1.6v.8h-1.6zM152.9 114h1.6v.7h-1.6zM152.9 116.5h1.6v.8h-1.6zM152.9 119h1.6v.8h-1.6zM153 112.9v.6M153.4 115.1h.6v.4l-.6 .6h.6M153.4 112.5h.7l-.5 1M153.4 117.7h.6v.3l-.6 .6h.6"/>
<path d="M153.4 106.7h.3v-.1h-.3v.4M153.4 109.3h.3v-.2h-.3v.4M153.4 114.3h.3v-.1h-.3v.4M153.4 116.9h.3v-.2h-.3v.4M153.4 111.8h.3v-.2h-.3v.5M153.4 119.4h.3v-.1h-.3v.4M153.5 107.4v1.1M153.5 110v1M153.5 106.7l.2 .3M153.5 109.3l.2 .2M153.5 114.3l.2 .3M153.5 116.9l.2 .2"/>
<path d="M153.5 111.8l.2 .3M153.5 119.4l.2 .3M153.6 107.9l.4 .6M153.6 110.4l.4 .6M153.8 100.4h.3l.3 .3v.5l-.2 .2h-.4zM153.9 106.6h.1l-.1 .4h.1M153.9 109.1h.1v.4l-.1-.1M153.9 114.2h.2l-.2 .4M153.9 111.6v.3h.2M154 107.4l-.5 .6M154 110l-.5 .6M154 116.7h-.1l.1 .4h-.1"/>
<path d="M154 119.3h-.1v.3l.1 .1v-.3l-.1 .1M154 111.7v.4M154.5 107.5l.2-.1a.54 .54 0 0 1 .3 .5 .54 .54 0 0 1-.3 .6l-.3-.2zM154.5 110.1l.2-.1a.54 .54 0 0 1 .3 .5 .54 .54 0 0 1-.3 .5l-.3-.2zM154.6 115.1l.3 .1v.7l-.2 .2-.3-.2v-.7zM154.6 112.5l.3 .2v.7l-.2 .1-.3-.1v-.7zM154.6 117.6l.3 .2v.6l-.2 .2-.3-.2v-.6zM155 115.2h.7l-.4 .4h.2l.2 .2-.1 .4h-.6M155.3 110.4l.3-.2v1M155.3 111.2h.6M155.4 100.6l-.2-.2-.4 .3 .1 .6h.5M156.1 116.2h.1"/>
<path d="M156.3 110.2h.5l.1 .1-.6 .9h.6M156.4 112.7h-.6v.4h.6v.5h-.6M156.4 118.2h.3M156.4 115.2h.7l-.2 .4a.35 .35 0 0 1 .2 .3 .35 .35 0 0 1-.2 .3h-.5M156.7 112.7l.3 1 .3-1M156.7 109.1l.3-.2h1.3v.7h-1.6zM156.7 116.8l.3-.3h1.3v.8h-1.6zM156.7 111.7l.3-.3h1.3v.8h-1.6zM156.7 114.2l.3-.2h1.3v.7h-1.6zM156.7 119h1.6v.8h-1.6zM156.9 117.8h-.5v1M157.1 118.8l.4-1 .3 1"/>
<path d="M157.1 110.2l.4 1 .3-1M157.2 118.4h.4M157.2 109.1l.3 .1v.2l-.2 .1zM157.2 111.6l.3 .1v.3l-.2 .1zM157.2 114.2l.3 .1v.2l-.2 .1zM157.2 116.7l.3 .1v.3h-.2zM157.4 115.2l.3 1 .3-1M157.5 119.3h-.3v.3h.3M157.6 112.7h.4l.2 .2v.6l-.3 .2h-.3zM157.7 119.3v.4M157.7 109.1h.1l-.1 .4h.1M157.7 111.6h.1v.5l-.1-.1"/>
<path d="M157.7 119.7h.1M157.7 114.3v-.1h.1v.1h-.1v.3l.1-.3M157.7 116.7v.3h.2M157.8 116.8v.3M158.1 110.2h.5a.58 .58 0 0 1 .1 .6 .58 .58 0 0 1-.6 .4zM158.4 115.2h.3l.3 .5-.4 .5h-.2zM158.6 117.8v1l-.6-1v1M159.2 112.8l-.4-.1-.2 .2v.6l.4 .2 .2-.1M159.7 110.2a.5 .5 0 0 0-.5 .2 .5 .5 0 0 0-.1 .6l.3 .2 .3-.1M159.9 115.3l-.4-.1a.52 .52 0 0 0-.2 .7 .52 .52 0 0 0 .6 .3M96.7 125.4l1 .2-1 .4M96.7 121.2h1l-1 .6h1"/>
<path d="M96.7 122.3h1M96.7 124.6l.2-.1h.5l.3 .1v.5h-1zM96.8 123.4l-.1 .3 .2 .3h.7v-.6M97.7 127.5h-1l.3 .3M97.7 126.3v.6l-.6-.6-.4 .2 .1 .4M97.7 127.3v.5M99.1 124.8h.8l.2 .2v.2M100.1 124.1h-1l.4 .3M100.1 123.9v.5M101.7 121l2.2 2.1M101.7 126.1l2.2 2.1M101.9 120.8l2.1 2.1"/>
<path d="M101.9 125.9l2.1 2.1M107.8 135.8l-.5-.1-.1 .2 .1 .3 .4 .1 .1 .3-.2 .1h-.4M108.2 136.2h.3M108.6 135.7h-.4v1h.4M109.1 136.2h.4l.1-.4-.5-.1v1M109.3 136.2l.3 .5M110 135.7v1M110.4 136.7l.3-1 .4 1M110.5 136.5h.5M111.4 135.7v1h.5M111.6 121.9h1M112.2 129.5h13.2"/>
<path d="M112.2 129h13.2v6.2h-12.7l-.5-.5zM112.2 134.7h13.2M112.3 124.4a.59 .59 0 0 1 .6 .3 .59 .59 0 0 1-.2 .7h-.4zM112.6 121.2l1.1 .7-1.1 .9zM112.8 135.7h.6M113.1 135.7v1M113.3 124.7l.3-.3v1M113.3 125.4h.5M113.7 121.2v1.6M113.7 121.9h.9M113.9 135.7h.2a.6 .6 0 0 1 0 1h-.2a.6 .6 0 0 1 0-1zM114.4 131.3l-1.6 1.5"/>
<path d="M114.5 131.4l-1.5 1.5M115.5 135.7v.1M115.5 136.1v.6M116 136.7v-1l.4 .8 .2-.8v1M117 136.7l.3-1 .4 1M117 131.3l-1.6 1.5M117.1 131.4l-1.6 1.5M117.2 136.5h.4M118.4 133.6v.9h-.3M118.6 135.8l-.3-.1-.3 .3v.5l.3 .2h.3M118.8 120.8h.9a.54 .54 0 0 1-.4 .5 .54 .54 0 0 1-.6-.2zM118.8 133.6h.6l-.3 .3 .3 .1v.5h-.6"/>
<path d="M119.5 131.3l-1.6 1.5M119.6 131.4l-1.5 1.5M119.7 122.6v.7l-.7-.7-.3 .3 .1 .3M119.7 121.7v.6l-.7-.6-.3 .1 .1 .5M120.3 135.8l-.3-.1-.3 .4 .3 .6h.4v-.4h-.2M120.3 121.2h.8v1.6h-.8zM120.7 121.8l.2-.1v.2l-.4-.2v.2h.2M120.7 135.7h.6l-.3 .4h.2l.1 .5-.2 .1h-.4M120.7 122.3l-.1-.3-.1 .3h.4M120.9 122l-.2 .2M121.2 124.5v-.7l.4 .3v-.2l.2-.1 .4 .1-.1 .6M121.2 123v-.7l.4 .4 .2-.4h.3l.1 .2-.1 .5"/>
<path d="M121.2 121.4l1 .4-1 .3M121.2 120.8l.3-.2h.5l.2 .1v.4h-1zM122.1 131.3l-1.6 1.5M122.1 123.4h.1M122.1 131.4l-1.5 1.5M122.7 135.7v.9l-.3 .1M122.8 121.2h.5l.3 .3v1.3h-.8zM123 122.1l.4-.1 .1 .3h-.5zM123.2 121.7l.1 .2h-.3v-.2h.4l.1 .2M123.2 135.8h.6v.3l-.6 .6h.6M123.8 120.8h1a.54 .54 0 0 1-.4 .5 .54 .54 0 0 1-.6-.2zM124.2 135.9l.3-.2a.58 .58 0 0 1-.1 1l-.2-.1z"/>
<path d="M124.6 131.3l-1.6 1.5M124.7 131.4l-1.5 1.5M124.8 122.6v.7l-.7-.7-.3 .3 .1 .3M124.8 121.7v.6l-.7-.6-.3 .1 .1 .5M125.4 121.2h.8v1.6h-.8zM125.7 121.7l.1 .2h-.2v-.2h.3l.1 .2M125.8 122.3l-.1-.3-.1 .3h.4M126 136.2l.4-.1 .1-.2-.2-.2h-.3v1h.5v-.4l-.2-.1M126 122l-.2 .2M126.3 124.5v-.7l.4 .3v-.2l.2-.1 .4 .1-.1 .6M126.3 123v-.7l.4 .4 .2-.4h.2l.2 .2-.1 .5M126.3 121.4l1 .4-1 .3"/>
<path d="M126.3 120.8l.2-.2h.6l.2 .1v.4h-1zM126.9 135.9l.4-.2a.6 .6 0 0 1 0 1l-.4-.1zM127.2 123.4h.1M127.8 136.7l.4-1 .3 1M127.9 121.2h.5l.3 .3v1.3h-.8zM127.9 136.5h.5M128.1 122.3l.3-.1 .1 .3h-.4zM128.1 121.5h.3l.1 .1-.3 .1zM128.5 122h-.4l.2 .1M128.5 121.9v.2M128.8 136.2h.5l.1-.3-.6-.2v1M129.1 136.2l.3 .5"/>
<path d="M129.9 135.7h.2l.3 .3v.5l-.3 .2h-.2zM136.3 125.6h.4l.1-.2-.2-.3h-.3v1.1h.4l.2-.4-.3-.2M137.7 122.3l.6-.6h.9v3h-1.5zM137.8 125.3l-.2-.2a.61 .61 0 0 0-.2 1.1l.4-.1M138.1 120.2l.3-1 .3 1M138.4 123.3l.3 .1v.3h-.4zM138.4 125.6l-.2-.3 .2-.2 .3 .1v.4l-.5 .1 .1 .5h.4l.1-.4-.2-.2M138.7 123h-.4l.1 .1M138.7 122.9v.2M138.8 123.3l-.2 .3M139.2 125.5l.3-.4v1.1M139.2 126.2h.6"/>
<path d="M140.1 125.1h.7l-.5 1.1M140.3 122.5l.2-.2v1M140.3 126.3l.2-.2v1M140.3 123.3h.5M140.3 127.1h.5M140.5 135.7h-.4l-.1 .5 .5-.1 .1 .5-.2 .1h-.4M140.8 129.5h5.5M140.8 129h5.5v6.2h-5l-.5-.5zM140.8 134.7h5.5M140.9 135.7l.3 1 .3-1M141.3 122.3h.1a.52 .52 0 0 1 .4 .4 .52 .52 0 0 1-.4 .6l-.2-.4zM141.3 126.2l.1-.1a.52 .52 0 0 1 .4 .4 .52 .52 0 0 1-.4 .6l-.2-.4z"/>
<path d="M141.9 135.7a.52 .52 0 0 1 .6 .5 .52 .52 0 0 1-.6 .5zM142.3 122.3a.52 .52 0 0 1 .4 .4 .52 .52 0 0 1-.3 .6l-.3-.4zM142.3 126.1a.52 .52 0 0 1 .4 .4 .52 .52 0 0 1-.3 .6l-.3-.4zM143 122.3l.3 1 .4-1M143 126.1l.3 1 .4-1M143 131.3l-1.6 1.5M143.1 131.4l-1.6 1.5M143.2 133.6v.7l-.1 .2h-.3M143.4 123.6h2.8v1.8h-2.8zM143.5 135.8a.47 .47 0 0 0-.7 .4 .47 .47 0 0 0 .7 .5M144.1 121.9a.59 .59 0 0 1 .5 .4 .59 .59 0 0 1-.1 .6h-.4zM144.1 120.6h.4"/>
<path d="M144.1 124.5h.4M144.2 133.6h-.5v.4h.5v.4l-.1 .1h-.4M144.5 120.1v1.1M144.5 124v1.1M144.5 120.6l.6-.3v.8zM144.5 124.5l.6-.4v.8zM144.8 122.5l.2-.2v1M144.8 126.3l.2-.2v1M144.8 123.3h.5M144.8 127.1h.5M144.8 135.7h.2a.6 .6 0 0 1 0 1h-.2a.6 .6 0 0 1 0-1zM145 121.9h.7l-.4 1"/>
<path d="M145.1 120.6h.5M145.1 124.5h.5M145.5 131.3l-1.5 1.5M145.7 135.7v.9l.2 .1 .4-.1v-.9M145.7 131.4l-1.6 1.5M145.9 135.7h.5l-.3 .4 .3 .1v.5h-.5M146.2 122.3h-.5v.4h.5l.1 .3-.3 .3-.3-.2M146.2 126.1h-.5v.4h.5l.1 .3-.3 .3-.3-.2M146.6 135.7h.5M146.7 122.3h.1a.52 .52 0 0 1 .4 .4 .52 .52 0 0 1-.3 .6l-.3-.4zM146.7 126.2l.1-.1a.52 .52 0 0 1 .4 .4 .52 .52 0 0 1-.3 .6l-.3-.4zM146.9 135.7v1"/>
<path d="M147.3 135.7h.6l-.4 .4 .4 .1v.5h-.6M147.6 122.7h.5v.6M147.6 126.5h.5v.6M147.6 122.6v.7M147.6 126.4v.7M147.8 129.5h5.5M147.8 129h5.5v6.2h-5.1l-.4-.5zM147.8 134.7h5.5M148.1 122.7h.4v.6M148.1 126.5h.4v.6M148.2 135.7l.4 1 .3-1M148.8 123.3l.4-1 .3 1"/>
<path d="M148.8 127.1l.4-1 .3 1M148.9 122.9h.5M148.9 126.7h.5M149.9 135.7h.3l.3 .3v.5l-.3 .2h-.3zM150 131.3l-1.6 1.5M150.1 131.4l-1.5 1.5M150.2 133.6v.9h-.4M151.1 133.6h-.3a.73 .73 0 0 0-.1 .9h.4l.1-.5-.4-.1-.2 .2M151.5 135.8l-.2-.1-.4 .3v.5l.4 .2h.2M152.5 123.1l.2-.2v1M152.5 123.9h.5M152.5 131.3l-1.6 1.5"/>
<path d="M152.6 131.4l-1.5 1.5M152.7 120.2l-.2 .8h.5M152.9 135.7l.4 .2v.7l-.2 .1-.4-.1v-.7zM152.9 121.6h1.6v.7h-1.6zM153 120.6v.7M153.4 120.3h.7l-.5 1M153.4 122h.3v-.2h-.3v.4M153.5 122.9v1M153.5 122l.2 .2M153.6 123.3l.4 .6M153.7 135.7v.9l.3 .1h.3v-1M153.9 121.9v-.1v.4"/>
<path d="M153.9 122.2h.1M154 122.9l-.5 .5M154.1 120.6l.3-.3v1M154.1 122.9h.5l.1 .4-.6 .6h.6M154.1 125.5l.5-.1 .1 .4-.6 .6h.6M154.1 121.3h.6M154.5 120.3h.3l.1 .2v.6l-.2 .2h-.1l-.2-.2zM154.6 122.9a.52 .52 0 0 1 .4 .4 .52 .52 0 0 1-.3 .6l-.3-.3v-.6zM154.7 135.7h.6M155 135.7v1M155.1 122.9h.4l.2 .2-.7 .8h.7M155.1 125.5l.4-.1 .2 .2-.7 .8h.7"/>
<path d="M155.2 120.3h.3l.2 .3-.3 .7-.3-.2zM156.1 120.6v.6h.4M156.1 123.2v.6h.4M156.1 125.7v.6h.4M156.5 120.6v.7M156.5 123.2v.7M156.5 125.7v.7M156.7 121.6h1.6v.7h-1.6zM156.7 124.1h1.6v.8h-1.6zM156.9 125.4l.3 1 .3-1M156.9 120.7h.4M156.9 123.3h.4"/>
<path d="M157.5 120.3h-.6v1M157.5 122.9h-.6v1M157.5 121.8l-.3 .1v.2h.3M157.5 124.3l-.3 .1v.3h.3M157.7 121.8h.1l-.1 .4h.1M157.7 124.3h.1v.5l-.1-.1M158.6 120.4l.4-.1 .1 .3-.6 .7h.6M158.6 123.1l.2-.2v1M158.6 125.6l.2-.2v1M158.6 123.9h.5M158.6 126.4h.5M159.6 122.9h.1a.52 .52 0 0 1 .4 .4 .52 .52 0 0 1-.4 .6l-.1-.1-.1-.4z"/>
<path d="M159.6 125.5l.1-.1a.52 .52 0 0 1 .4 .5 .52 .52 0 0 1-.4 .5l-.1-.1-.1-.3zM160 120.3h-.4l-.1 .4h.5v.5h-.5M160.3 120.3l.4 1 .3-1M160.3 122.9l.4 1 .3-1M160.3 125.4l.4 1 .3-1"/>
<circle cx="100" cy="85.9" r="3.2"/>
<circle cx="100" cy="85.9" r="1.4"/>
<circle cx="158" cy="85.9" r="3.2"/>
<circle cx="158" cy="85.9" r="1.4"/>
<circle cx="106.4" cy="118.1" r=".34"/>
<circle cx="133.3" cy="113.4" r="1.14"/>
<circle cx="137.3" cy="115.6" r="1.14"/>
<circle cx="139.8" cy="115.6" r="1.14"/>
<circle cx="100" cy="135" r="3.2"/>
<circle cx="100" cy="135" r="1.4"/>
<circle cx="103" cy="122" r="1.57"/>
<circle cx="103" cy="127" r="1.57"/>
<circle cx="113.7" cy="132.1" r="1.14"/>
<circle cx="116.3" cy="132.1" r="1.14"/>
<circle cx="118.8" cy="132.1" r="1.14"/>
<circle cx="121.3" cy="132.1" r="1.14"/>
<circle cx="123.9" cy="132.1" r="1.14"/>
<circle cx="142.3" cy="132.1" r="1.14"/>
<circle cx="144.9" cy="132.1" r="1.14"/>
<circle cx="149.3" cy="132.1" r="1.14"/>
<circle cx="151.8" cy="132.1" r="1.14"/>
<circle cx="158" cy="135" r="3.2"/>
<circle cx="158" cy="135" r="1.4"/>
</g>
<g fill="#840000">
<path d="M113.9 120.8h2.6v2.3h-2.6z"/>
<path d="M109.7 120.8h2.5v2.3h-2.5z"/>
<path d="M120.3 120.7h.7l.1 .8h-.8z"/>
<path d="M120.2 122.5l.2-.2 .7 .1v.7l-.8 .1z"/>
<path d="M104.5 87.9h1v1.8h-1z"/>
<path d="M107 87.9h1v1.8h-1z"/>
<path d="M104.5 82.1h1v1.8h-1z"/>
<path d="M107 82.1h1v1.8h-1z"/>
<path d="M109.5 82.1h1v1.8h-1z"/>
<path d="M142.7 120.1h1v1.2h-1z"/>
<path d="M142.7 123.9h1v1.2h-1z"/>
<path d="M137 121.8h.9v.9h-.9z"/>
<path d="M137 123.8h.9v.7h-.9z"/>
<path d="M139 122.9h.9v.7h-.9z"/>
<path d="M122.8 120.7h.8l.1 .9h-.9z"/>
<path d="M122.8 122.3h.9l-.1 .9-.9-.1z"/>
<path d="M127.9 122.3h.8v.9l-.9-.1z"/>
<path d="M127.9 120.7h.8v.9h-.8z"/>
<path d="M125.4 122.3l.8 .1-.1 .8-.8-.1v-.6z"/>
<path d="M125.4 120.7h.7l.1 .8h-.8z"/>
<path d="M157.9 111.4l.7-.1 .1 .9-.7 .1z"/>
<path d="M156.3 111.4l.8-.1 .1 .8-.2 .2h-.6z"/>
<path d="M157.9 116.5l.7-.1 .1 .9h-.7z"/>
<path d="M156.3 114l.8-.1 .1 .7-.2 .2h-.6z"/>
<path d="M157.9 114l.7-.1 .1 .8-.7 .1z"/>
<path d="M154.1 113.9h.8l-.1 .9-.7-.1z"/>
<path d="M152.5 113.9l.8 .1-.1 .8-.7-.1z"/>
<path d="M146 120.1h1v1.2h-1z"/>
<path d="M146 116.2h1v1.3h-1z"/>
<path d="M142.7 116.2h1v1.3h-1z"/>
<path d="M146 123.9h1v1.2h-1z"/>
<path d="M143.8 108.2h1v1.1h-1z"/>
<path d="M143.8 105.9h1v1.1h-1z"/>
<path d="M141.5 108.2h1.1v1.1h-1.1z"/>
<path d="M141.5 105.9h1.1v1.1h-1.1z"/>
<path d="M139.2 108.2h1.1v1.1h-1.1z"/>
<path d="M156.3 116.5l.8-.1 .1 .8-.2 .1h-.6z"/>
<path d="M156.3 119h.8l.1 .8-.8 .1z"/>
<path d="M157.9 119h.7l.1 .8-.7 .1z"/>
<path d="M152.5 121.5l.8 .1-.1 .8-.7-.1z"/>
<path d="M152.5 116.5h.8l-.1 .8h-.7z"/>
<path d="M154.1 116.4h.8l-.1 .9h-.7z"/>
<path d="M152.5 119h.8l-.1 .9-.7-.1z"/>
<path d="M154.1 119h.8l-.1 .9-.7-.1z"/>
<path d="M157.9 121.6l.7-.1 .1 .8-.7 .1z"/>
<path d="M156.3 121.6l.8-.1 .1 .8-.8 .1z"/>
<path d="M156.3 124.1l.8-.1 .1 .9-.8 .1z"/>
<path d="M157.9 124.1l.7-.1 .1 .9-.7 .1z"/>
<path d="M154.1 121.5h.8l-.1 .9-.7-.1z"/>
<path d="M156.3 108.9l.8-.1 .1 .8-.2 .1h-.6z"/>
<path d="M157.9 108.9l.7-.1 .1 .8-.7 .1z"/>
<path d="M154.1 106.3h.8l-.1 .9-.7-.1z"/>
<path d="M152.5 106.3h.7l.1 .8-.8 .1z"/>
<path d="M154.1 108.8h.8l-.1 .9-.7-.1z"/>
<path d="M152.5 108.8l.8 .1-.1 .8-.7-.1z"/>
<path d="M152.5 111.4l.7-.1 .1 .9-.8 .1z"/>
<path d="M154.1 111.3h.8l-.1 1-.7-.1z"/>
<path d="M143.8 103.6h1v1.1h-1z"/>
<path d="M143.8 101.3h1v1.1h-1z"/>
<path d="M143.8 99.1h1v1.1h-1z"/>
<path d="M141.5 101.3h1.1v1.1h-1.1z"/>
<path d="M141.5 99.1h1.1v1.1h-1.1z"/>
<path d="M141.5 103.6h1.1v1.1h-1.1z"/>
<path d="M139.2 103.6h1.1v1.1h-1.1z"/>
<path d="M139.2 101.3h1.1v1.1h-1.1z"/>
<path d="M139.2 99.1h1.1v1.1h-1.1z"/>
<path d="M136.9 103.6h1.1v1.1h-1.1z"/>
<path d="M139.2 105.9h1.1v1.1h-1.1z"/>
<path d="M136.9 108.2h1.1v1.1h-1.1z"/>
<path d="M136.9 105.9h1.1v1.1h-1.1z"/>
<path d="M134.6 108.2h1.1v1.1h-1.1z"/>
<path d="M134.6 105.9h1.1v1.1h-1.1z"/>
<path d="M134.6 103.6h1.1v1.1h-1.1z"/>
<path d="M136.9 101.3h1.1v1.1h-1.1z"/>
<path d="M136.9 99.1h1.1v1.1h-1.1z"/>
<path d="M134.6 101.3h1.1v1.1h-1.1z"/>
<path d="M134.6 99.1h1.1v1.1h-1.1z"/>
<path d="M142.6 87.9h1v1.8h-1z"/>
<path d="M145.1 87.9h1v1.8h-1z"/>
<path d="M147.6 87.9h1v1.8h-1z"/>
<path d="M150.2 87.9h1v1.8h-1z"/>
<path d="M152.7 87.9h1v1.8h-1z"/>
<path d="M109.5 87.9h1v1.8h-1z"/>
<path d="M112.1 87.9h1v1.8h-1z"/>
<path d="M114.6 87.9h1v1.8h-1z"/>
<path d="M112.1 82.1h1v1.8h-1z"/>
<path d="M114.6 82.1h1v1.8h-1z"/>
<path d="M117.2 82.1h1v1.8h-1z"/>
<path d="M119.7 82.1h1v1.8h-1z"/>
<path d="M117.2 87.9h1v1.8h-1z"/>
<path d="M119.7 87.9h1v1.8h-1z"/>
<path d="M122.2 87.9h1v1.8h-1z"/>
<path d="M124.8 87.9h1v1.8h-1z"/>
<path d="M127.3 87.9h1v1.8h-1z"/>
<path d="M122.2 82.1h1v1.8h-1z"/>
<path d="M124.8 82.1h1v1.8h-1z"/>
<path d="M127.3 82.1h1v1.8h-1z"/>
<path d="M134.9 87.9h1v1.8h-1z"/>
<path d="M137.5 87.9h1v1.8h-1z"/>
<path d="M140 87.9h1v1.8h-1z"/>
<path d="M137.5 82.1h1v1.8h-1z"/>
<path d="M140 82.1h1v1.8h-1z"/>
<path d="M129.9 87.9h1v1.8h-1z"/>
<path d="M132.4 87.9h1v1.8h-1z"/>
<path d="M129.9 82.1h1v1.8h-1z"/>
<path d="M132.4 82.1h1v1.8h-1z"/>
<path d="M134.9 82.1h1v1.8h-1z"/>
<path d="M142.6 82.1h1v1.8h-1z"/>
<path d="M145.1 82.1h1v1.8h-1z"/>
<path d="M147.6 82.1h1v1.8h-1z"/>
<path d="M150.2 82.1h1v1.8h-1z"/>
<path d="M152.7 82.1h1v1.8h-1z"/>
</g>
<g fill="none" stroke="#008484" stroke-width=".2">
<path d="M101.9 86.2h.8l.2 .4M102.8 82.5l.1-.2 .4 .2v.3l-.5 .5h.5M102.8 88.6l.3-.2v1M102.8 89.4h.5M102.9 85.3v.6l-.6-.6h-.3v.5M104.3 83.2h-.8v5.4h.8M133.4 97.9h12.6v12.6h-12.6zM134 97.7h-.8v.8M142.1 90.9v.9l-.3 .1M142.1 94.7v.9l-.3 .2M142.6 91.4h.5l.1-.3-.6-.2v1M142.6 95.2h.5l.1-.3-.6-.2v1.1"/>
<path d="M143.6 91.2l.3-.3v1M143.6 94.8l.4-.1 .2 .2-.6 .9h.6M143.6 91.9h.6M145.4 95v.6M145.4 95.6a.7 .7 0 0 0 .7 .7M146.1 90.5h1.4a.7 .7 0 0 1 .7 .7M146.1 92.5h1.4M146.1 94.3h1.4M146.1 96.3h1.4M146.1 90.5a.74 .74 0 0 0-.7 .7v.6a.7 .7 0 0 0 .7 .7M146.1 94.3a.7 .7 0 0 0-.7 .7M147.5 94.3a.7 .7 0 0 1 .7 .7"/>
<path d="M148.2 91.8a.7 .7 0 0 1-.7 .7M148.2 95.6a.7 .7 0 0 1-.7 .7M148.2 91.2v.6M148.2 95v.6M148.9 96h.3M149.1 98.6v.6l-.3 .4h-.2M149.4 95.6h-.5v1M149.5 94l-.3-.1-.3 .2v.6l.3 .2 .3-.1v-.3h-.2M149.6 99.1h.4l.1-.5h-.5v1M149.7 96.6l.3-1 .3 1M149.7 96.3h.6M149.9 94.4h.5l.1-.3-.2-.2h-.4v1"/>
<path d="M150.4 98.6h.7l-.3 .3 .3 .2v.3l-.3 .2-.4-.1M150.9 93.9v1M151.2 95.6v1l-.5-1v1M151.6 93.9h.2a.6 .6 0 0 1 0 1h-.2a.6 .6 0 0 1 0-1zM152.3 98.8v.6M152.3 99.4a.7 .7 0 0 0 .7 .7M152.4 94h.6v.3l-.6 .6h.6M153 98.1h1.4M153 98.1a.7 .7 0 0 0-.7 .7M153.6 93.9l-.2 .7h.6M153.8 94.2v.7M153.9 92.4h.7l.3 .4"/>
<path d="M153.9 83.2h.7v5.4h-.7M154.4 98.1a.7 .7 0 0 1 .7 .7M154.6 88.4h.6l-.4 .3 .4 .2v.4h-.6M154.8 82.3l-.2 .7h.7M154.9 91.8l-1-.4v.6M155.1 82.6v.7M155.1 98.8v.6M155.1 99.4a.7 .7 0 0 1-.7 .7M155.4 89.5h5.3v5.2h-2.7v-2.7h-2.6zM155.4 93.3v1.4h1.4M155.7 82.4l.2-.1 .2 .2-.1 .8h-.3l-.1-.2zM155.8 99.9h.6a.67 .67 0 0 1-.2 .9h-.2a.67 .67 0 0 1-.2-.9z"/>
<path d="M155.8 92.4l.6-.1v-.4h-.6v1M156.1 88.8l-.1 .2h-.3l-.1-.5h.5v.7l-.1 .1-.3 .1M156.3 98.1h-.5v.5h.5l.1 .4-.2 .1h-.4M156.4 90.3a.52 .52 0 0 0-.6 .2 .52 .52 0 0 0 .1 .7h.5v-.4h-.2M156.6 98.1l.3 1 .4-1M156.7 91.9l.2 1 .2-.8 .3 .8 .1-1M156.8 90.8h.4l.2-.5-.2-.1h-.4v1M157.6 98.1a.52 .52 0 0 1 .6 .5 .52 .52 0 0 1-.6 .5zM157.8 90.2v1M158 92.4l.6-.2-.1-.3h-.5v1M158.2 92.4l.4 .5M158.5 90.2l.4 .1v.8h-.6a.67 .67 0 0 1 .2-.9z"/>
<path d="M158.8 92.9l.3-1 .4 1M158.9 92.5h.5M159.1 99.8h-.5v1M159.2 98.2a.47 .47 0 0 0-.7 .4 .47 .47 0 0 0 .7 .5M159.3 90.3l.1-.1h.3l.1 .4-.6 .6h.6M159.8 91.9v1h.4M160.2 90.2h.6l-.3 .4h.3v.2v.4l-.6-.1M160.6 92.9v-1l.3 .6 .4-.6v1M160.9 99.8v1l-.6-1v1M98.3 119.4h9.9v10.2h-9.9zM98.8 119.4v10.2M98.8 119.1h-.8v.5"/>
<path d="M100.3 119.4v10.2M105.2 119.4v10.2M108.3 116.4h.6v.4l-.6 .5h.6M109.8 116.3h-.5v.5l.1-.1 .4 .1v.5h-.5M110.2 116.8l.4-.1 .1 .6M110.2 116.7v.6M110.7 116.8v-.1h.4v.6M110.9 119.8h5.7v4.3h-5.7M111.6 116.8l.4-.1v.6M111.6 116.7v.6M112 116.8l.1-.1h.3v.6M113.6 116.7l.5 .6"/>
<path d="M114.1 116.7l-.5 .6M115.2 116.4l.3-.1 .3 .3-.7 .7h.7M116.6 116.3h-.4l-.1 .5 .5-.1 .1 .5-.1 .1h-.5M117.2 116.8l.4-.1v.6M117.2 116.7v.6M117.6 116.8l.1-.1h.3v.6M118.5 116.8l.3-.1 .1 .6M118.5 116.7v.6M118.9 116.8v-.1h.4l.1 .6M120.5 118.8l.3-.2 .3 .1v.4l-.1 .1-.5-.2v-.3l-.1-.1-.3 .2 .1 .3 .2 .1 .1-.2M120.6 116.8h.3M121 116.3h-.4v1"/>
<path d="M121.1 119.5l-.5 .4M121.3 117.3l.3-1 .4 1M121.4 117h.5M122.7 119.9l.5-.4 .5 .3v.3h-1zM122.9 116.3v1l-.6-1v1M123.1 118.6l.2 .2v.2l-.2 .2-.4-.1v-.3l.2-.2 .8 .2v.3M125.6 118.6l.3 .2v.2l-.3 .2-.3-.1-.1-.3 .2-.2 .8 .2v.3M126.2 119.5l-.5 .4M127.7 119.7l.3-.2h.5l.2 .1v.4h-1zM127.8 117.6l.6-.1 .3 .2a.54 .54 0 0 1-.4 .4 .54 .54 0 0 1-.6-.2zM128.7 118.8h-1l.4 .2M128.7 118.4v.6"/>
<path d="M129.6 112h5.1v9.8h-5.1zM132.8 119l1 .4-1 .3M133.8 118.4h-1l.4 .4M133.8 120l-.5 .3M133.8 118.2v.6M135.4 118.3v.7h.5M135.6 118.2h.8M135.6 112.9h5.7M136.4 118.8h-.8v-6.4h5.7v6.4h-.8M136.5 119.6v.8M137.3 119.9h.3M137.8 119.4h-.5v1"/>
<path d="M138 118.2h.9M138 118.8h.9M138.1 112.5v.7l-.4 .3M138.8 112.4l-.2 .8h.6M139 112.9v.6M139.6 119.4v1l-.6-1v1M140.5 118.2h.8M146.4 115.9h-3.8v2h3.8M146.4 119.7h-3.8v2h3.8M146.6 111.3v.9l.2 .1 .3-.1v-.9M147.6 111.5l.3-.2v1M147.6 112.3h.5"/>
<path d="M147.9 116.3a.52 .52 0 0 1 .6 .5 .52 .52 0 0 1-.6 .5zM149.1 101.1v.7l-.3 .3h-.2M149.3 116.3l-.3 .1-.2 .8 .3 .1 .3-.1-.2-.5-.3 .1-.1 .1M149.6 101.6h.4l.1-.4-.5-.1v1M150.4 106.7h.5l.1-.4-.2-.1h-.4v1M150.4 109.2h.5l.1-.3-.2-.2h-.4v1M150.4 111.8h.5l.1-.4-.2-.1h-.4v1M150.4 116.8h.5l.1-.3-.2-.2h-.4v1M150.4 119.4h.5l.1-.4-.2-.1h-.4v1M150.4 114.3h.5l.1-.3-.2-.2h-.4v1M150.7 106.7l.3 .5M150.7 109.2l.3 .5"/>
<path d="M150.7 111.8l.3 .5M150.7 116.8l.3 .5M150.7 119.4l.3 .5M150.7 114.3l.3 .5M150.8 101l-.3 .8h.6M150.9 101.4v.7M151.4 106.3l.4-.1 .1 .1-.5 .9h.5M151.4 108.7h.5l-.3 .4h.3v.5l-.1 .1-.4-.1M151.4 113.8h.6l-.4 1M151.6 111.2l-.2 .7h.6M151.9 116.3h-.5v.5l.4-.1 .1 .5-.1 .1h-.4M151.9 118.9l-.4 .1-.1 .7 .2 .2 .3-.2-.1-.5-.4 .1v.2"/>
<path d="M151.9 111.6v.7M152.3 101.3v.6M152.3 102a.7 .7 0 0 0 .7 .7M153 100.1h1.4M153 100.7h1.4M153 102.6h1.4M153 100.7a.7 .7 0 0 0-.7 .7M153.5 106.2h.5M153.5 107.3h.5M153.5 108.7h.5M153.5 109.8h.5M153.5 117.4h.5"/>
<path d="M153.5 118.9h.5M153.5 120h.5M153.5 112.4h.5M153.5 111.3h.5M153.5 116.3h.5M153.5 113.8h.5M153.5 114.9h.5M154.4 100.7a.7 .7 0 0 1 .7 .7M155 115.1h.7l-.4 .3 .3 .1 .1 .4-.2 .2-.5-.1M155.1 101.3v.6M155.1 102a.7 .7 0 0 1-.7 .7M155.3 110.2l.3-.2v1"/>
<path d="M155.3 111h.6M155.8 101.8l.2-.4v1M155.8 102.4h.6M156.1 116v.1M156.3 110.1l.4-.1 .2 .2-.6 .8h.6M156.4 112.5h-.6v.5l.4-.1 .2 .1v.5h-.6M156.4 118.1h.3M156.4 115.1h.7l-.3 .3 .2 .1 .1 .4-.2 .2-.5-.1M156.7 112.5l.3 1 .3-1M156.7 101.5l.4-.1 .2 .2-.6 .8h.6M156.9 117.6h-.5v1M156.9 100.3l.6-.1-.1-.4h-.5v1"/>
<path d="M157.1 110l.4 1 .3-1M157.1 118.6l.4-1 .3 1M157.1 100.3l.4 .5M157.2 118.3h.4M157.4 115.1l.3 1 .3-1M157.4 118.9h.2M157.4 119.9h.2M157.5 101.4l.4 1 .3-1M157.6 112.5h.3l.3 .3v.5l-.3 .2h-.3zM158.1 110a.52 .52 0 0 1 .6 .5 .52 .52 0 0 1-.6 .5zM158.3 108.5h-2.3v1.5h2.3M158.3 111.1h-2.3v1.4h2.3"/>
<path d="M158.3 113.6h-2.3v1.5h2.3M158.3 116.2h-2.3v1.4h2.3M158.4 115.1h.2l.4 .4-.4 .6h-.2zM158.6 101.4a.52 .52 0 0 1 .6 .5 .52 .52 0 0 1-.6 .5zM158.6 117.6v1l-.6-1v1M158.6 100.2h.4M159.2 112.6l-.2-.1-.4 .3v.5l.4 .2h.2M159.3 116.3a.52 .52 0 0 1 .6 .5 .52 .52 0 0 1-.6 .5zM159.3 113.8a.52 .52 0 0 1 .6 .5 .52 .52 0 0 1-.6 .5zM159.3 108.7a.52 .52 0 0 1 .6 .5 .52 .52 0 0 1-.6 .5zM159.3 111.3a.52 .52 0 0 1 .6 .5 .52 .52 0 0 1-.6 .5zM159.3 100.8l.4-1 .3 1"/>
<path d="M159.4 100.5h.5M159.7 110.1a.47 .47 0 0 0-.6 .4 .47 .47 0 0 0 .6 .4M159.9 115.1a.45 .45 0 0 0-.6 .5 .45 .45 0 0 0 .6 .4M159.9 119l-.3-.1-.4 .4 .4 .6 .3-.1M160.2 101.5l-.4-.1-.3 .5 .3 .5h.4M160.2 108.8l.5-.1 .1 .2-.6 .8h.6M160.2 111.3h.6l-.3 .3 .3 .1v.4l-.1 .2-.5-.1M160.2 119.1l.4-.2v1M160.2 119.9h.6M160.5 116.2l-.3 .8h.7M160.5 114.2l-.3-.2 .5-.2 .1 .2-.6 .4v.2l.3 .2 .3-.2-.1-.4M160.8 116.7v.6"/>
<path d="M96.7 125.1h1.1v.5l-.3 .1h-.5l-.3-.3zM96.7 120.8h.8M96.7 122.3v.6M96.8 126.7l-.1-.2 .3-.3h.5l.3 .1-.1 .4M97.2 120.4v.8M97.2 127.9v.8M97.5 122.3l.3 .4h-1.1M97.7 123.3v.6h-.4l-.6-.6v.6M97.8 124.2l-1.1 .3 1.1 .3M101.3 122l.1 .6M101.4 121.3l-.1 .7M101.7 126h.1"/>
<path d="M101.8 125.7l.1 .1M102.3 123.5l.7 .1 .7-.1M102.3 120.4l.7-.1 .7 .1M103.9 128.3h.1M104.1 128.1h.1M104.5 121.3l.1 .7-.1 .6M106.4 124v.6l-.4 .4M106.8 124.2l.3-.2v1M106.8 125h.6M111.4 128.6v.1M111.4 128.9v.7M111.8 129.6v-1l.4 .7 .3-.7v1"/>
<path d="M111.9 134.8v.8h.5M112.2 128.9h13.2v6.4h-13.2zM112.2 129.5h13.2M112.2 134.7h13.2M112.3 121.4a.52 .52 0 0 1 .6 .5 .52 .52 0 0 1-.6 .5zM112.8 129.6l.4-1 .3 1M112.9 129.3h.5M113.1 127l-.4-.1-.2 .2 .1 .2 .3 .1 .2 .3-.2 .2-.4-.1M113.2 136.4l1 .6M113.3 121.7l.3-.3v1M113.3 122.4h.5M113.5 127.4h.3"/>
<path d="M113.7 137.9l-.1-.5-.3-.1-.1 .2v.4h1M114 126.9h-.5v1h.5M114.2 137.3l-.5 .4M114.2 136.4l-1 .6M114.4 127.4h.5l.1-.3-.6-.2v1M114.4 128.7l-.4-.1-.2 .4 .3 .6 .3-.1M114.7 127.4l.3 .5M115.5 126.9v1M115.7 137.4v.5M115.7 137.7h1M115.7 136.5l1 .7M115.8 127.9l.2-1 .4 1"/>
<path d="M115.9 127.7h.4M116.1 128.6h-.3a.5 .5 0 0 0-.3 .6 .5 .5 0 0 0 .6 .3l.1-.4h-.2M116.6 128.6h.6l-.4 .3 .4 .2-.1 .4-.5 .1v-.1M116.7 126.9v1h.5M116.7 136.5l-1 .7M118.3 137.3v.4a.5 .5 0 0 0 .6 .2 .5 .5 0 0 0 .3-.6l-.4-.1v.3M118.3 136.3h1l-1 .5h1M118.3 135.3a.59 .59 0 0 1 .7 0 .59 .59 0 0 1 .3 .5h-1zM118.4 129.6v1h-.3M118.6 128.6v.9l-.3 .1M118.8 129.6h.6l-.3 .4 .3 .1v.5h-.6M119 127.4l-.2 .4h-.5v-.3l.5-.4-.1-.2-.2 .1v.3l.6 .6"/>
<path d="M119 128.7h.6v.3l-.6 .6h.6M120.1 128.6h.4v.2v.6l-.1 .2h-.2l-.2-.2zM120.2 121.8v.4M120.4 126.9v1M120.6 120.1v-.4l-.1-.2-.3 .1-.1 .5h1M120.8 135.4l.8-.1 .2 .3-.2 .2h-.6l-.2-.1zM121.2 136.5l.3-.3 .3 .2v.4h-1l.1-.5 .3 .1v.4M121.2 121.8v.4M121.3 137.8l-.1-.6h-.3l-.1 .6h1M121.6 126.9l-1 1.3M121.7 129h.4l.2-.2-.2-.2h-.4v1h.4l.2-.1v-.4l-.2-.1M122 124.5h.5l.1-.4-.2-.1h-.4v1"/>
<path d="M122.1 126.9h.1a.6 .6 0 0 1 0 1h-.1a.6 .6 0 0 1 0-1zM122.5 122.8v-2.3h1.4v2.3M122.8 128.6l.5 .1a.67 .67 0 0 1-.1 .9l-.5-.1zM123 124.5h.3l.2-.2v-.3h-.2h-.3v1l.6-.2-.1-.3h-.2M123.5 126.9h.6M123.7 129.6l.3-1 .3 1M123.8 136.5l.2-.3 .3 .2v.4h-1l.1-.5 .4 .1v.4M123.8 129.3h.5M123.8 137.8v-.6h-.4l-.1 .6h1M123.8 126.9v1M124 124h.2a.54 .54 0 0 1 .3 .5 .54 .54 0 0 1-.3 .5l-.2-.1-.1-.4zM124.3 135.6h-1l.3 .2"/>
<path d="M124.3 135.3v.5M124.6 126.9l.4 .2v.7l-.4 .1a.6 .6 0 0 1 0-1zM124.7 129.1l.5-.1-.1-.4h-.4v1M124.9 129.1l.3 .5M125.3 121.8v.4M125.7 128.6h.3l.2 .3v.5l-.3 .2h-.2zM125.7 120.1v-.4l-.2-.2-.2 .1-.1 .5h1M126.3 121.8v.4M127.1 124.5h.5v-.4l-.1-.1h-.4v1M127.6 122.8v-2.3h1.4v2.3M128.1 124.5h.3l.2-.2v-.3h-.2h-.3v1l.6-.2-.1-.3h-.2M129 124.2l.3-.2v1"/>
<path d="M129 125h.6M130.5 123.5h.6M130.8 123.5v1M131 121.8h-.6v.5h.5l.1 .5h-.6M131.3 121.8l.3 1.1 .3-1.1M131.5 124h.5v-.4l-.5-.1v1M131.6 124l.4 .5M132.2 121.8h.3l.3 .3v.5l-.3 .3h-.3zM132.4 123.5v1M132.9 124.5v-1l.3 .7 .4-.7v1M133.3 120.6v-.5l-.1-.1-.3 .1-.1 .5h1M133.8 121.9l-.2-.1-.4 .3v.5l.4 .3 .2-.1"/>
<path d="M135.2 122.9l.3-.2a.6 .6 0 0 1 0 1h-.1a.6 .6 0 0 1-.2-.8zM135.3 123.4l.6 .4M136.1 120.1h.8M136.2 122.9l.3-.2v1M136.2 123.7h.5M137 121.7h2.2v.9M138.1 120.4l.3-1 .3 1M138.1 120.1h.5M139.2 123.9v.9h-1.5M140.1 120.1h.8M140.4 134.8v.8h.5M140.7 129.5h5.7"/>
<path d="M140.7 134.7h.7M141.4 135.3h-.7v-6.4h5.7v6.4h-.8M141.8 136.7h.8M142.1 136.2v.8M142.4 127.8h-.5l-.1 .5 .4-.2 .2 .2v.4h-.6M142.7 127.8l.4 1 .2-1M143.1 135.3h.9M143.1 134.7h.9M143.2 129.6v.8l-.1 .2h-.3M143.7 127.8h.2l.3 .2v.5l-.3 .3h-.2zM144.2 129.6h-.5v.5h.5v.4l-.1 .1h-.4M144.6 136.7h.7"/>
<path d="M145.3 127.8h-.3l-.3 .2v.5l.3 .3 .3-.1M145.6 134.7h.8M146.4 123.5h-3.8v2h3.8M147.5 134.8v.8h.5M147.7 129.5h5.7M147.7 134.7h.8M147.9 120.1a.52 .52 0 0 1 .6 .5 .52 .52 0 0 1-.6 .6zM147.9 124a.52 .52 0 0 1 .6 .5 .52 .52 0 0 1-.6 .5zM148.1 127.8h.5l-.3 .3 .3 .2v.4h-.5M148.5 135.3h-.8v-6.4h5.7v6.4h-.8M148.7 136.7h.8M148.8 124h.7l-.4 1"/>
<path d="M149.1 128.7v.1M149.2 136.2v.8M149.3 120.1h-.4l-.1 .5 .4-.1 .2 .5-.2 .2-.4-.1M149.5 127.8h.6l-.4 .3 .4 .2v.4h-.6M150.1 135.3h.9M150.1 134.7h.9M150.2 129.6v1h-.4M150.4 121.9h.5l.1-.3-.2-.2h-.4v1M150.4 127.8l.3 1 .3-1M150.7 121.9l.3 .5M151.1 129.6a.68 .68 0 0 0-.4 1h.4l.1-.5-.4-.1-.2 .2M151.4 121.7l.3-.3v1"/>
<path d="M151.4 127.8h.2l.3 .2v.5l-.3 .3h-.2zM151.4 122.4h.5M151.5 136.7h.8M152.6 134.7h.8M153 127.8h-.3l-.3 .2v.5l.3 .3 .3-.1M153.5 121.4h.5M153.5 122.5h.5M157.4 121.4h.2M157.4 122.4h.2M157.4 125h.2M157.4 124h.2M159.9 121.5l-.3-.1-.4 .4 .4 .6 .3-.1"/>
<path d="M159.9 124h-.3l-.4 .4 .4 .6 .3-.1M160.2 121.5l.5-.1 .1 .2-.6 .8h.6M160.2 124h.6l-.3 .3 .3 .1v.4l-.1 .2-.5-.1"/>
<circle cx="103" cy="127" r="1.74"/>
</g>
<g fill="none" stroke="#008484" stroke-width=".34">
<path d="M97 96.4v-.9l.6 .5 .1-.4h.7l.1 .2v.5l-.1 .1M97.1 97a.5 .5 0 0 0 .2 .8 .84 .84 0 0 0 1.2-.5l-.1-.4h-.6v.4M97.6 99.6a.52 .52 0 0 0 .2 .7h.4l.2-.1v-.6M99.5 95.9v.9M99.5 99.4h1.6M99.5 98.6h1.6M99.5 96.4h1.6M100.3 98.6v.8M100.6 97.2v.7M101.1 97l-1.6 .5 1.6 .5M97 109.7h.2M97 104.1h.2"/>
<path d="M97 107.3v.8M97 107.7h1.5M97.1 106l.4-.2 .9 .2a.54 .54 0 0 1-.4 .8h-.5a.55 .55 0 0 1-.4-.8zM97.5 109.7h1M97.5 104.1h1M97.8 112.8l-.1-.9h-.5l-.2 .3v.6h1.5M97.8 111.3l-.1-.8h-.6l-.1 .8h1.5M97.8 100.9l.3 .8 .3-.1 .1-.2-.1-.5M98.5 102.3h-1.5l1.1 .5-1.1 .5h1.5M98.5 100.9h-.8l-.2 .3 .1 .4M98.5 111.9l-.7 .5M99.5 110.7h1.6l-1.6 .8h1.6"/>
<path d="M99.5 108.1v.7h1.6v-.7M99.5 105.2v.8h1.6M99.5 101.2v.7h1.6v-.7M99.5 109.7h1.6M99.5 112.3h1.6M99.5 109.3v.9M99.7 102.5l-.1 .1a.5 .5 0 0 0 .3 .8 .67 .67 0 0 0 .8 0 .67 .67 0 0 0 .2-.9M100.3 107.4v-.6l-.5-.2-.3 .2v.6h1.6M100.3 101.4v.5M100.3 105.5v.5M100.3 108.3v.5M100.6 104.1v.6"/>
<path d="M101.1 103.9l-1.6 .5 1.6 .5M101.1 106.6l-.8 .5"/>
</g>
<g fill="#840084">
<path d="M137 121.8h.9v.9h-.9z"/>
<path d="M137 123.8h.9v.7h-.9z"/>
<path d="M136.1 114.5h2.2v2.2h-2.2z"/>
<path d="M142.7 116.2h1v1.3h-1z"/>
<path d="M140 82.1h1v1.8h-1z"/>
<path d="M142.6 82.1h1v1.8h-1z"/>
<path d="M109.7 120.8h2.5v2.3h-2.5z"/>
<path d="M101.6 120.6h2.6v2.7h-2.6z"/>
<path d="M104.5 82.1h1v1.8h-1z"/>
<path d="M113.9 120.8h2.6v2.3h-2.6z"/>
<path d="M122.8 122.3h.9l-.1 .9-.9-.1z"/>
<path d="M120.3 120.7h.7l.1 .8h-.8z"/>
<path d="M120.2 122.5l.2-.2 .7 .1v.7l-.8 .1z"/>
<path d="M122.8 120.7h.8l.1 .9h-.9z"/>
<path d="M127.9 122.3h.8v.9l-.9-.1z"/>
<path d="M127.9 120.7h.8v.9h-.8z"/>
<path d="M125.4 122.3l.8 .1-.1 .8-.8-.1v-.6z"/>
<path d="M125.4 120.7h.7l.1 .8h-.8z"/>
<path d="M112.6 131h2.2v2.2h-2.2z"/>
<path d="M156.3 108.9l.8-.1 .1 .8-.2 .1h-.6z"/>
<path d="M157.9 108.9l.7-.1 .1 .8-.7 .1z"/>
<path d="M156.3 111.4l.8-.1 .1 .8-.2 .2h-.6z"/>
<path d="M154.1 106.3h.8l-.1 .9-.7-.1z"/>
<path d="M152.5 106.3h.7l.1 .8-.8 .1z"/>
<path d="M154.1 108.8h.8l-.1 .9-.7-.1z"/>
<path d="M152.5 108.8l.8 .1-.1 .8-.7-.1z"/>
<path d="M143.8 103.6h1v1.1h-1z"/>
<path d="M143.8 101.3h1v1.1h-1z"/>
<path d="M143.8 99.1h1v1.1h-1z"/>
<path d="M141.5 101.3h1.1v1.1h-1.1z"/>
<path d="M141.5 99.1h1.1v1.1h-1.1z"/>
<path d="M139.2 101.3h1.1v1.1h-1.1z"/>
<path d="M139.2 99.1h1.1v1.1h-1.1z"/>
<path d="M141.5 103.6h1.1v1.1h-1.1z"/>
<path d="M139.2 108.2h1.1v1.1h-1.1z"/>
<path d="M139.2 105.9h1.1v1.1h-1.1z"/>
<path d="M139.2 103.6h1.1v1.1h-1.1z"/>
<path d="M153.9 98.4h.7l.2 .2v1l-.2 .2h-.7z"/>
<path d="M152.6 98.6l.2-.2h.8v1.4h-.8l-.2-.1z"/>
<path d="M152.8 100.9h.8v1.5h-.8l-.2-.2-.1-.9z"/>
<path d="M153.9 100.9h.7l.2 .3v.9l-.2 .3h-.7z"/>
<path d="M156.3 121.6l.8-.1 .1 .8-.8 .1z"/>
<path d="M156.3 124.1l.8-.1 .1 .9-.8 .1z"/>
<path d="M157.9 124.1l.7-.1 .1 .9-.7 .1z"/>
<path d="M148.1 131h2.2v2.2h-2.2z"/>
<path d="M142.7 120.1h1v1.2h-1z"/>
<path d="M146 120.1h1v1.2h-1z"/>
<path d="M146 116.2h1v1.3h-1z"/>
<path d="M146 123.9h1v1.2h-1z"/>
<path d="M139 122.9h.9v.7h-.9z"/>
<path d="M157.9 116.5l.7-.1 .1 .9h-.7z"/>
<path d="M156.3 116.5l.8-.1 .1 .8-.2 .1h-.6z"/>
<path d="M156.3 114l.8-.1 .1 .7-.2 .2h-.6z"/>
<path d="M157.9 114l.7-.1 .1 .8-.7 .1z"/>
<path d="M154.1 116.4h.8l-.1 .9h-.7z"/>
<path d="M154.1 113.9h.8l-.1 .9-.7-.1z"/>
<path d="M156.3 119h.8l.1 .8-.8 .1z"/>
<path d="M157.9 119h.7l.1 .8-.7 .1z"/>
<path d="M157.9 121.6l.7-.1 .1 .8-.7 .1z"/>
<path d="M154.1 121.5h.8l-.1 .9-.7-.1z"/>
<path d="M152.5 121.5l.8 .1-.1 .8-.7-.1z"/>
<path d="M152.5 119h.8l-.1 .9-.7-.1z"/>
<path d="M154.1 119h.8l-.1 .9-.7-.1z"/>
<path d="M157.9 111.4l.7-.1 .1 .9-.7 .1z"/>
<path d="M152.5 111.4l.7-.1 .1 .9-.8 .1z"/>
<path d="M154.1 111.3h.8l-.1 1-.7-.1z"/>
<path d="M152.5 116.5h.8l-.1 .8h-.7z"/>
<path d="M152.5 113.9l.8 .1-.1 .8-.7-.1z"/>
<path d="M142.7 123.9h1v1.2h-1z"/>
<path d="M141.2 131h2.2v2.2h-2.2z"/>
<path d="M114.6 87.9h1v1.8h-1z"/>
<path d="M117.2 87.9h1v1.8h-1z"/>
<path d="M119.7 87.9h1v1.8h-1z"/>
<path d="M122.2 87.9h1v1.8h-1z"/>
<path d="M143.8 108.2h1v1.1h-1z"/>
<path d="M143.8 105.9h1v1.1h-1z"/>
<path d="M141.5 108.2h1.1v1.1h-1.1z"/>
<path d="M141.5 105.9h1.1v1.1h-1.1z"/>
<path d="M136.9 108.2h1.1v1.1h-1.1z"/>
<path d="M134.6 108.2h1.1v1.1h-1.1z"/>
<path d="M134.6 105.9h1.1v1.1h-1.1z"/>
<path d="M136.9 105.9h1.1v1.1h-1.1z"/>
<path d="M136.9 103.6h1.1v1.1h-1.1z"/>
<path d="M136.9 101.3h1.1v1.1h-1.1z"/>
<path d="M136.9 99.1h1.1v1.1h-1.1z"/>
<path d="M134.6 103.6h1.1v1.1h-1.1z"/>
<path d="M134.6 101.3h1.1v1.1h-1.1z"/>
<path d="M134.6 99.1h1.1v1.1h-1.1z"/>
<path d="M132.4 87.9h1v1.8h-1z"/>
<path d="M134.9 87.9h1v1.8h-1z"/>
<path d="M137.5 87.9h1v1.8h-1z"/>
<path d="M104.5 87.9h1v1.8h-1z"/>
<path d="M107 87.9h1v1.8h-1z"/>
<path d="M109.5 87.9h1v1.8h-1z"/>
<path d="M112.1 87.9h1v1.8h-1z"/>
<path d="M127.3 87.9h1v1.8h-1z"/>
<path d="M129.9 87.9h1v1.8h-1z"/>
<path d="M124.8 87.9h1v1.8h-1z"/>
<path d="M107 82.1h1v1.8h-1z"/>
<path d="M109.5 82.1h1v1.8h-1z"/>
<path d="M112.1 82.1h1v1.8h-1z"/>
<path d="M119.7 82.1h1v1.8h-1z"/>
<path d="M122.2 82.1h1v1.8h-1z"/>
<path d="M124.8 82.1h1v1.8h-1z"/>
<path d="M132.4 82.1h1v1.8h-1z"/>
<path d="M134.9 82.1h1v1.8h-1z"/>
<path d="M137.5 82.1h1v1.8h-1z"/>
<path d="M114.6 82.1h1v1.8h-1z"/>
<path d="M117.2 82.1h1v1.8h-1z"/>
<path d="M127.3 82.1h1v1.8h-1z"/>
<path d="M129.9 82.1h1v1.8h-1z"/>
<path d="M152.7 82.1h1v1.8h-1z"/>
<path d="M145.7 91l.2-.2h.7v1.4h-.7l-.2-.3z"/>
<path d="M145.7 94.8l.2-.2h.7v1.4h-.7l-.2-.2z"/>
<path d="M147 94.6l.8 .1 .2 .3v.6l-.3 .4h-.7z"/>
<path d="M140 87.9h1v1.8h-1z"/>
<path d="M142.6 87.9h1v1.8h-1z"/>
<path d="M147 90.8h.8l.2 .4v.6l-.3 .4h-.7z"/>
<path d="M145.1 87.9h1v1.8h-1z"/>
<path d="M147.6 87.9h1v1.8h-1z"/>
<path d="M150.2 87.9h1v1.8h-1z"/>
<path d="M145.1 82.1h1v1.8h-1z"/>
<path d="M147.6 82.1h1v1.8h-1z"/>
<path d="M150.2 82.1h1v1.8h-1z"/>
<path d="M152.7 87.9h1v1.8h-1z"/>
<path d="M155.9 92.5h1.7v1.6h-1.7z"/>
<path d="M156.2 90.2l.6-.3v1.7a.85 .85 0 0 1-.8-.5 .85 .85 0 0 1 .2-.9z"/>
<path d="M156.8 89.9a.85 .85 0 0 1 .8 .9 .85 .85 0 0 1-.8 .8z"/>
<path d="M158.7 92.7l.6-.2v1.7a.85 .85 0 0 1-.8-.6 .85 .85 0 0 1 .2-.9z"/>
<path d="M159.3 92.5a.85 .85 0 0 1 .9 .8 .85 .85 0 0 1-.9 .9z"/>
<path d="M158.7 90.2l.6-.3v1.7a.85 .85 0 0 1-.8-.5 .85 .85 0 0 1 .2-.9z"/>
<path d="M159.3 89.9a.85 .85 0 0 1 .9 .9 .85 .85 0 0 1-.9 .8z"/>
<circle cx="137.2" cy="118.1" r=".55"/>
<circle cx="133.4" cy="116.8" r=".8"/>
<circle cx="130.9" cy="119.4" r=".8"/>
<circle cx="139.8" cy="115.6" r="1.14"/>
<circle cx="139.8" cy="118.1" r=".55"/>
<circle cx="105.5" cy="114" r="1.57"/>
<circle cx="100" cy="135" r="3.2"/>
<circle cx="102.9" cy="127" r="1.31"/>
<circle cx="100" cy="85.9" r="3.2"/>
<circle cx="106.2" cy="85.9" r=".97"/>
<circle cx="105" cy="87.2" r=".55"/>
<circle cx="105" cy="84.7" r=".55"/>
<circle cx="116.2" cy="132.1" r="1.14"/>
<circle cx="118.8" cy="132.1" r="1.14"/>
<circle cx="121.3" cy="132.1" r="1.14"/>
<circle cx="123.8" cy="132.1" r="1.14"/>
<circle cx="158" cy="135" r="3.2"/>
<circle cx="151.8" cy="134.6" r=".55"/>
<circle cx="151.8" cy="132.1" r="1.14"/>
<circle cx="149.2" cy="134.6" r=".55"/>
<circle cx="142.3" cy="134.6" r=".55"/>
<circle cx="144.8" cy="132.1" r="1.14"/>
<circle cx="144.8" cy="134.6" r=".55"/>
<circle cx="125.3" cy="87.2" r=".55"/>
<circle cx="112.6" cy="87.2" r=".55"/>
<circle cx="115.1" cy="87.2" r=".55"/>
<circle cx="117.7" cy="87.2" r=".55"/>
<circle cx="120.2" cy="87.2" r=".55"/>
<circle cx="122.7" cy="87.2" r=".55"/>
<circle cx="132.9" cy="87.2" r=".55"/>
<circle cx="135.4" cy="87.2" r=".55"/>
<circle cx="138" cy="87.2" r=".55"/>
<circle cx="105.5" cy="94" r="1.57"/>
<circle cx="127.8" cy="87.2" r=".55"/>
<circle cx="130.4" cy="87.2" r=".55"/>
<circle cx="125.4" cy="114" r="1.57"/>
<circle cx="125.4" cy="94" r="1.57"/>
<circle cx="130.9" cy="114.3" r=".8"/>
<circle cx="107.5" cy="87.2" r=".55"/>
<circle cx="110" cy="87.2" r=".55"/>
<circle cx="107.5" cy="84.7" r=".55"/>
<circle cx="110" cy="84.7" r=".55"/>
<circle cx="112.6" cy="84.7" r=".55"/>
<circle cx="120.2" cy="84.7" r=".55"/>
<circle cx="122.7" cy="84.7" r=".55"/>
<circle cx="125.3" cy="84.7" r=".55"/>
<circle cx="132.9" cy="84.7" r=".55"/>
<circle cx="135.4" cy="84.7" r=".55"/>
<circle cx="138" cy="84.7" r=".55"/>
<circle cx="115.1" cy="84.7" r=".55"/>
<circle cx="117.7" cy="84.7" r=".55"/>
<circle cx="127.8" cy="84.7" r=".55"/>
<circle cx="130.4" cy="84.7" r=".55"/>
<circle cx="151.9" cy="85.9" r=".97"/>
<circle cx="153.2" cy="87.2" r=".55"/>
<circle cx="150.7" cy="84.7" r=".55"/>
<circle cx="153.2" cy="84.7" r=".55"/>
<circle cx="145.6" cy="87.2" r=".55"/>
<circle cx="140.5" cy="87.2" r=".55"/>
<circle cx="143.1" cy="87.2" r=".55"/>
<circle cx="140.5" cy="84.7" r=".55"/>
<circle cx="143.1" cy="84.7" r=".55"/>
<circle cx="145.6" cy="84.7" r=".55"/>
<circle cx="148.1" cy="87.2" r=".55"/>
<circle cx="150.7" cy="87.2" r=".55"/>
<circle cx="148.1" cy="84.7" r=".55"/>
<circle cx="158" cy="85.9" r="3.2"/>
</g>
<g fill="none" stroke="#840000" stroke-width=".25">
<path d="M105 88.6l.5 .3M107.5 88.4h.1M112.6 83.1h-1l-.3 .3v5.9M115.1 83v.4M115.1 83.3l2.6 2.6h8.2l.5 .5v2.7M122.7 88.4h.1M122.7 83h.3l.8 .8v1.3l.4 .3h1.8l.5 .5h1.9l.5 .5v3.8l2.6 2.5v2.9l1 .9h13.6M122.7 83.1v.2M125.3 88.4h.1M125.3 83h.2l.9 .8v.7l1 .9h1.2l.7 .9v3.7l1.6 1.4h15.2M125.3 88.8v-.3l-2.1-2.1h-8.5l-.9 .8v1.7M125.3 83.1v.3"/>
<path d="M132.1 95.2h12.7M135.4 88.6l.5 .3M137.2 99.1l.3 .2v.3M138.5 94h13.2l5.8 5.8v7.6l-1.1 1.1h-2.3l-.4 .4v6.7M139.8 99.6v9.2M139.9 99.6l2.1 2.1M140.5 83.1h.1M142 99.6v9.2M142 99.7l-2.2 2.2M145.6 83.1h.1M146.1 96.5h.1M146.1 95.2v1.3"/>
<path d="M147.5 95.2h4.9l4.6 4.8v7.2l-.7 .7h-3.8l-1.3 1.3v7.3l2.9 2.9h.9l1.3-1.3h1.2l.8-.8v-.5M147.5 91.4l-.1 1.3h-14M148.1 83v.4l1.1 1.1v8.2l.9 .9h1.8l6.2 6.2v8.1l2 1.8v16.7l-2.6 2.5h-35.5l-.7 .6v2.6M150.7 88.8v3.8l.5 .5h.8l6.6 6.6v8l1.9 1.9v17l-2.8 2.8h-33l-.9 .8v1.9M152.5 99.1h.5M133.4 101.6v3.8l1 1h.8M137 101.9l-1.1 1 1.3 1.2M137.1 106.4l-1.2 1.2M137.2 104.1l-1.3 1.3 1.1 1h7.3M137.2 104.1h.3M137.5 101.9h.1M137.5 101.9l-1.3-1.2h-.3l-.7 .7v.5h7.4l1 1-1.3 1.2"/>
<path d="M137.5 101.9l4.5 4.5M137.5 104.4l2 2M138.5 100.7l1-1.1h3l1.1 1.1-1.3 1.2M138.5 100.7l-1 .9v5l1 1M138.5 100.7l1.2 1.2M139.5 101.9l-2 2M139.7 106.4l-1.2 1.2M139.8 101.9h.1M139.8 106.4l2.2 2.2M140 101.9l2 2M142 104.4l-2 2M142 104.1h.3"/>
<path d="M142 101.9l-4.5 4.5M142 106.6l-2.1 2.2M142.3 104.1l1.3 1.3-1 1M142.4 106.4l1.2 1.2-1.1 1.2h-2.9l-1.1-1.2M144.3 108.8l.5 .4M144.8 111.8h-10.1l-1.3 1.2v3.8M152.5 111.8h.4M152.5 114.3h.4M152.5 116.8h.4M152.5 106.7h.4M152.5 109.2h.4M152.8 118.1h.1"/>
<path d="M152.9 119.4h-2.4l-1.5 1.6v2.5l-3.1 3.1h-6l-1.4-1.5v-1.8l-1-1M154.5 111.8h2.2M154.5 114.3h2.2M154.5 116.8h2.2M154.5 106.7h.5M154.5 109.2h2.2M158.3 109.2v.5l-.8 .8v1.8l1.6 1.6v4l-.3 .2h-.5l-2.8 2.5h-5l-1.1 1.2v1.9l-3.3 3.3h-29.9l-1-1v-4.1h.4M158.3 111.8l1.3 1.3v6.8l-.8 .7h-.8l-2.5 2.6h-4.3l-5.1 5.1h-3.8M158.3 114.3v.5l-.8 .8h-3.2l-.6-.6M158.3 119.4h.5M120.7 121.2h2.5M120.7 122.8v1.7"/>
<path d="M123.2 122.8v.4l-1.9 1.9v.6M125.8 121.2h2.5M125.8 122.8v1.7M128.3 122.8v2.3l-.7 .6h-3.8M139.5 123.2v2.3l.6 .6h5.7l.6-.7v-.9M143.1 124.5h.5M152.9 121.9h-3v2l-3.6 3.6h-31.8l-.8 .8v3.8M154.5 121.9h.5M156.8 124.5h-6.3l-1.3 1.2v2.6M158.3 121.9h.5M158.3 124.5h.5"/>
</g>
<g fill="none" stroke="#840000" stroke-width="1">
<path d="M105 83h3.3l.5 .4v6.9l.1 .1M144.8 99.1l-1.7-1.7h-11l-1.5-1.5v-2.9l-2.5-2.5h-26.8l-2.2 2.2v36l8.6 8.5h26.3l5.1-5.1h3.2M144.8 99.1v4.6l-.5 .4M144.8 99.1h8.2M154.3 99.1h.7l1.3 1.2v3.8l-1.3 1.3h-2.8l-2.3 2.4v8.2l-3.4 3.4-.1 1.2M137.2 115.6v-1.7l.9-.9h4.2l.8 1v10.5M139.8 115.6h1.2l1 1v5.7l-1 .9h-1.5M153 101.6h-4.4l-2.5 2.5v6.4h-15.2M154.3 101.6l.7 .7v1.4l-.4 .4h-2.8l-3.2 3.3v8.2l-1.2 1.2h-1M137.2 124.5h-1.3v1.2M137.2 124.5v1.2h-1.3M137.2 124.5l-1.3 1.2"/>
<path d="M137.5 124.2l-.4 .3"/>
</g>
<path d="M137.2 99.1h-6.3v10.1l-2.6 2.6v3.8l-1.2 1.2h-5.8l-5.1 5.1h-1M102.9 121.9h8M105.5 125.7h2.5v2.6h-2.5zM108 125.7l-.7 .7v.6h-4.4" fill="none" stroke="#840000" stroke-width="2"/>
<g fill="#840000">
<path d="M113.9 120.8h2.6v2.3h-2.6z"/>
<path d="M109.7 120.8h2.5v2.3h-2.5z"/>
<path d="M120.3 120.7h.7l.1 .8h-.8z"/>
<path d="M120.2 122.5l.2-.2 .7 .1v.7l-.8 .1z"/>
<path d="M141.5 105.9h1.1v1.1h-1.1z"/>
<path d="M141.5 103.6h1.1v1.1h-1.1z"/>
<path d="M139.2 103.6h1.1v1.1h-1.1z"/>
<path d="M136.9 103.6h1.1v1.1h-1.1z"/>
<path d="M143.8 108.2h1v1.1h-1z"/>
<path d="M143.8 105.9h1v1.1h-1z"/>
<path d="M141.5 108.2h1.1v1.1h-1.1z"/>
<path d="M139.2 108.2h1.1v1.1h-1.1z"/>
<path d="M139.2 105.9h1.1v1.1h-1.1z"/>
<path d="M141.5 101.3h1.1v1.1h-1.1z"/>
<path d="M141.5 99.1h1.1v1.1h-1.1z"/>
<path d="M139.2 101.3h1.1v1.1h-1.1z"/>
<path d="M139.2 99.1h1.1v1.1h-1.1z"/>
<path d="M136.9 101.3h1.1v1.1h-1.1z"/>
<path d="M136.9 99.1h1.1v1.1h-1.1z"/>
<path d="M134.6 101.3h1.1v1.1h-1.1z"/>
<path d="M134.6 99.1h1.1v1.1h-1.1z"/>
<path d="M136.9 108.2h1.1v1.1h-1.1z"/>
<path d="M136.9 105.9h1.1v1.1h-1.1z"/>
<path d="M134.6 108.2h1.1v1.1h-1.1z"/>
<path d="M134.6 105.9h1.1v1.1h-1.1z"/>
<path d="M134.6 103.6h1.1v1.1h-1.1z"/>
<path d="M142.7 120.1h1v1.2h-1z"/>
<path d="M142.7 123.9h1v1.2h-1z"/>
<path d="M137 121.8h.9v.9h-.9z"/>
<path d="M137 123.8h.9v.7h-.9z"/>
<path d="M139 122.9h.9v.7h-.9z"/>
<path d="M122.8 120.7h.8l.1 .9h-.9z"/>
<path d="M122.8 122.3h.9l-.1 .9-.9-.1z"/>
<path d="M127.9 122.3h.8v.9l-.9-.1z"/>
<path d="M127.9 120.7h.8v.9h-.8z"/>
<path d="M125.4 122.3l.8 .1-.1 .8-.8-.1v-.6z"/>
<path d="M125.4 120.7h.7l.1 .8h-.8z"/>
<path d="M157.9 111.4l.7-.1 .1 .9-.7 .1z"/>
<path d="M156.3 111.4l.8-.1 .1 .8-.2 .2h-.6z"/>
<path d="M157.9 116.5l.7-.1 .1 .9h-.7z"/>
<path d="M156.3 114l.8-.1 .1 .7-.2 .2h-.6z"/>
<path d="M157.9 114l.7-.1 .1 .8-.7 .1z"/>
<path d="M157.9 119h.7l.1 .8-.7 .1z"/>
<path d="M154.1 113.9h.8l-.1 .9-.7-.1z"/>
<path d="M152.5 113.9l.8 .1-.1 .8-.7-.1z"/>
<path d="M146 120.1h1v1.2h-1z"/>
<path d="M146 116.2h1v1.3h-1z"/>
<path d="M142.7 116.2h1v1.3h-1z"/>
<path d="M146 123.9h1v1.2h-1z"/>
<path d="M156.3 108.9l.8-.1 .1 .8-.2 .1h-.6z"/>
<path d="M157.9 108.9l.7-.1 .1 .8-.7 .1z"/>
<path d="M154.1 106.3h.8l-.1 .9-.7-.1z"/>
<path d="M154.1 108.8h.8l-.1 .9-.7-.1z"/>
<path d="M152.5 108.8l.8 .1-.1 .8-.7-.1z"/>
<path d="M152.5 111.4l.7-.1 .1 .9-.8 .1z"/>
<path d="M154.1 111.3h.8l-.1 1-.7-.1z"/>
<path d="M147 90.8h.8l.2 .4v.6l-.3 .4h-.7z"/>
<path d="M145.7 91l.2-.2h.7v1.4h-.7l-.2-.3z"/>
<path d="M145.7 94.8l.2-.2h.7v1.4h-.7l-.2-.2z"/>
<path d="M147 94.6l.8 .1 .2 .3v.6l-.3 .4h-.7z"/>
<path d="M147.6 87.9h1v1.8h-1z"/>
<path d="M150.2 87.9h1v1.8h-1z"/>
<path d="M152.7 87.9h1v1.8h-1z"/>
<path d="M152.8 100.9h.8v1.5h-.8l-.2-.2-.1-.9z"/>
<path d="M143.8 103.6h1v1.1h-1z"/>
<path d="M143.8 101.3h1v1.1h-1z"/>
<path d="M143.8 99.1h1v1.1h-1z"/>
<path d="M157.9 121.6l.7-.1 .1 .8-.7 .1z"/>
<path d="M156.3 121.6l.8-.1 .1 .8-.8 .1z"/>
<path d="M156.3 124.1l.8-.1 .1 .9-.8 .1z"/>
<path d="M157.9 124.1l.7-.1 .1 .9-.7 .1z"/>
<path d="M154.1 121.5h.8l-.1 .9-.7-.1z"/>
<path d="M153.9 98.4h.7l.2 .2v1l-.2 .2h-.7z"/>
<path d="M152.6 98.6l.2-.2h.8v1.4h-.8l-.2-.1z"/>
<path d="M153.9 100.9h.7l.2 .3v.9l-.2 .3h-.7z"/>
<path d="M152.5 106.3h.7l.1 .8-.8 .1z"/>
<path d="M156.3 116.5l.8-.1 .1 .8-.2 .1h-.6z"/>
<path d="M156.3 119h.8l.1 .8-.8 .1z"/>
<path d="M152.5 121.5l.8 .1-.1 .8-.7-.1z"/>
<path d="M152.5 116.5h.8l-.1 .8h-.7z"/>
<path d="M154.1 116.4h.8l-.1 .9h-.7z"/>
<path d="M152.5 119h.8l-.1 .9-.7-.1z"/>
<path d="M154.1 119h.8l-.1 .9-.7-.1z"/>
<path d="M109.5 87.9h1v1.8h-1z"/>
<path d="M112.1 87.9h1v1.8h-1z"/>
<path d="M114.6 87.9h1v1.8h-1z"/>
<path d="M112.1 82.1h1v1.8h-1z"/>
<path d="M114.6 82.1h1v1.8h-1z"/>
<path d="M117.2 82.1h1v1.8h-1z"/>
<path d="M119.7 82.1h1v1.8h-1z"/>
<path d="M117.2 87.9h1v1.8h-1z"/>
<path d="M119.7 87.9h1v1.8h-1z"/>
<path d="M122.2 87.9h1v1.8h-1z"/>
<path d="M124.8 87.9h1v1.8h-1z"/>
<path d="M127.3 87.9h1v1.8h-1z"/>
<path d="M122.2 82.1h1v1.8h-1z"/>
<path d="M124.8 82.1h1v1.8h-1z"/>
<path d="M127.3 82.1h1v1.8h-1z"/>
<path d="M137.5 87.9h1v1.8h-1z"/>
<path d="M140 87.9h1v1.8h-1z"/>
<path d="M142.6 87.9h1v1.8h-1z"/>
<path d="M145.1 87.9h1v1.8h-1z"/>
<path d="M142.6 82.1h1v1.8h-1z"/>
<path d="M104.5 87.9h1v1.8h-1z"/>
<path d="M107 87.9h1v1.8h-1z"/>
<path d="M104.5 82.1h1v1.8h-1z"/>
<path d="M107 82.1h1v1.8h-1z"/>
<path d="M109.5 82.1h1v1.8h-1z"/>
<path d="M129.9 87.9h1v1.8h-1z"/>
<path d="M132.4 87.9h1v1.8h-1z"/>
<path d="M134.9 87.9h1v1.8h-1z"/>
<path d="M129.9 82.1h1v1.8h-1z"/>
<path d="M132.4 82.1h1v1.8h-1z"/>
<path d="M134.9 82.1h1v1.8h-1z"/>
<path d="M137.5 82.1h1v1.8h-1z"/>
<path d="M140 82.1h1v1.8h-1z"/>
<path d="M145.1 82.1h1v1.8h-1z"/>
<path d="M147.6 82.1h1v1.8h-1z"/>
<path d="M150.2 82.1h1v1.8h-1z"/>
<path d="M152.7 82.1h1v1.8h-1z"/>
</g>
<g fill="#c2c200">
<path d="M136.1 114.5h2.2v2.2h-2.2z"/>
<path d="M141.2 131h2.2v2.2h-2.2z"/>
<path d="M155.9 92.5h1.7v1.6h-1.7z"/>
<path d="M156.2 90.2l.6-.3v1.7a.85 .85 0 0 1-.8-.5 .85 .85 0 0 1 .2-.9z"/>
<path d="M156.8 89.9a.85 .85 0 0 1 .8 .9 .85 .85 0 0 1-.8 .8z"/>
<path d="M158.7 92.7l.6-.2v1.7a.85 .85 0 0 1-.8-.6 .85 .85 0 0 1 .2-.9z"/>
<path d="M159.3 92.5a.85 .85 0 0 1 .9 .8 .85 .85 0 0 1-.9 .9z"/>
<path d="M158.7 90.2l.6-.3v1.7a.85 .85 0 0 1-.8-.5 .85 .85 0 0 1 .2-.9z"/>
<path d="M159.3 89.9a.85 .85 0 0 1 .9 .9 .85 .85 0 0 1-.9 .8z"/>
<path d="M101.6 120.6h2.6v2.7h-2.6z"/>
<path d="M112.6 131h2.2v2.2h-2.2z"/>
<path d="M148.1 131h2.2v2.2h-2.2z"/>
<circle cx="137.2" cy="118.1" r=".55"/>
<circle cx="133.4" cy="116.8" r=".8"/>
<circle cx="130.9" cy="119.4" r=".8"/>
<circle cx="116.2" cy="132.1" r="1.14"/>
<circle cx="118.8" cy="132.1" r="1.14"/>
<circle cx="121.3" cy="132.1" r="1.14"/>
<circle cx="123.8" cy="132.1" r="1.14"/>
<circle cx="139.8" cy="115.6" r="1.14"/>
<circle cx="139.8" cy="118.1" r=".55"/>
<circle cx="151.9" cy="85.9" r=".97"/>
<circle cx="148.1" cy="87.2" r=".55"/>
<circle cx="148.1" cy="84.7" r=".55"/>
<circle cx="150.7" cy="84.7" r=".55"/>
<circle cx="153.2" cy="84.7" r=".55"/>
<circle cx="140.5" cy="87.2" r=".55"/>
<circle cx="143.1" cy="87.2" r=".55"/>
<circle cx="145.6" cy="87.2" r=".55"/>
<circle cx="140.5" cy="84.7" r=".55"/>
<circle cx="143.1" cy="84.7" r=".55"/>
<circle cx="145.6" cy="84.7" r=".55"/>
<circle cx="135.4" cy="87.2" r=".55"/>
<circle cx="138" cy="87.2" r=".55"/>
<circle cx="135.4" cy="84.7" r=".55"/>
<circle cx="138" cy="84.7" r=".55"/>
<circle cx="158" cy="85.9" r="1.4"/>
<circle cx="150.7" cy="87.2" r=".55"/>
<circle cx="153.2" cy="87.2" r=".55"/>
<circle cx="105.5" cy="114" r="1.57"/>
<circle cx="100" cy="135" r="1.4"/>
<circle cx="102.9" cy="127" r="1.31"/>
<circle cx="158" cy="135" r="1.4"/>
<circle cx="142.3" cy="134.6" r=".55"/>
<circle cx="144.8" cy="132.1" r="1.14"/>
<circle cx="144.8" cy="134.6" r=".55"/>
<circle cx="151.8" cy="134.6" r=".55"/>
<circle cx="151.8" cy="132.1" r="1.14"/>
<circle cx="149.2" cy="134.6" r=".55"/>
<circle cx="125.4" cy="114" r="1.57"/>
<circle cx="125.4" cy="94" r="1.57"/>
<circle cx="105.5" cy="94" r="1.57"/>
<circle cx="125.3" cy="87.2" r=".55"/>
<circle cx="127.8" cy="87.2" r=".55"/>
<circle cx="130.4" cy="87.2" r=".55"/>
<circle cx="132.9" cy="87.2" r=".55"/>
<circle cx="130.9" cy="114.3" r=".8"/>
<circle cx="100" cy="85.9" r="1.4"/>
<circle cx="106.2" cy="85.9" r=".97"/>
<circle cx="105" cy="87.2" r=".55"/>
<circle cx="107.5" cy="87.2" r=".55"/>
<circle cx="110" cy="87.2" r=".55"/>
<circle cx="105" cy="84.7" r=".55"/>
<circle cx="107.5" cy="84.7" r=".55"/>
<circle cx="110" cy="84.7" r=".55"/>
<circle cx="117.7" cy="87.2" r=".55"/>
<circle cx="120.2" cy="87.2" r=".55"/>
<circle cx="122.7" cy="87.2" r=".55"/>
<circle cx="117.7" cy="84.7" r=".55"/>
<circle cx="120.2" cy="84.7" r=".55"/>
<circle cx="112.6" cy="87.2" r=".55"/>
<circle cx="115.1" cy="87.2" r=".55"/>
<circle cx="112.6" cy="84.7" r=".55"/>
<circle cx="115.1" cy="84.7" r=".55"/>
<circle cx="122.7" cy="84.7" r=".55"/>
<circle cx="125.3" cy="84.7" r=".55"/>
<circle cx="127.8" cy="84.7" r=".55"/>
<circle cx="130.4" cy="84.7" r=".55"/>
<circle cx="132.9" cy="84.7" r=".55"/>
</g>
<g fill="#c2c2c2">
<circle cx="105.5" cy="125.7" r=".38"/>
<circle cx="106.7" cy="125.7" r=".38"/>
<circle cx="108" cy="125.7" r=".38"/>
<circle cx="108" cy="127" r=".38"/>
<circle cx="106.7" cy="127" r=".38"/>
<circle cx="105.5" cy="127" r=".38"/>
<circle cx="105.5" cy="128.3" r=".38"/>
<circle cx="106.7" cy="128.3" r=".38"/>
<circle cx="108" cy="128.3" r=".38"/>
<circle cx="138.5" cy="105.4" r=".38"/>
<circle cx="135.9" cy="105.4" r=".38"/>
<circle cx="135.9" cy="102.9" r=".38"/>
<circle cx="135.9" cy="107.6" r=".38"/>
<circle cx="132.1" cy="95.2" r=".38"/>
<circle cx="133.4" cy="101.6" r=".38"/>
<circle cx="133.4" cy="92.7" r=".38"/>
<circle cx="120.2" cy="83.1" r=".38"/>
<circle cx="127.8" cy="83.1" r=".38"/>
<circle cx="125.3" cy="88.6" r=".38"/>
<circle cx="126.4" cy="89.1" r=".38"/>
<circle cx="110" cy="83.1" r=".38"/>
<circle cx="115.1" cy="88.6" r=".38"/>
<circle cx="105" cy="88.6" r=".38"/>
<circle cx="113.8" cy="88.9" r=".38"/>
<circle cx="111.3" cy="89.3" r=".38"/>
<circle cx="125.8" cy="124.5" r=".38"/>
<circle cx="120.7" cy="124.5" r=".38"/>
<circle cx="123.8" cy="125.7" r=".38"/>
<circle cx="121.3" cy="125.7" r=".38"/>
<circle cx="141" cy="102.9" r=".38"/>
<circle cx="138.5" cy="102.9" r=".38"/>
<circle cx="138.5" cy="100.7" r=".38"/>
<circle cx="141" cy="100.7" r=".38"/>
<circle cx="135.9" cy="100.7" r=".38"/>
<circle cx="138.5" cy="94" r=".38"/>
<circle cx="144.8" cy="95.2" r=".38"/>
<circle cx="141" cy="105.4" r=".38"/>
<circle cx="143.6" cy="102.9" r=".38"/>
<circle cx="141" cy="107.6" r=".38"/>
<circle cx="138.5" cy="107.6" r=".38"/>
<circle cx="143.6" cy="100.7" r=".38"/>
<circle cx="143.6" cy="105.4" r=".38"/>
<circle cx="143.6" cy="107.6" r=".38"/>
<circle cx="152.5" cy="106.7" r=".38"/>
<circle cx="152.5" cy="109.2" r=".38"/>
<circle cx="152.5" cy="111.8" r=".38"/>
<circle cx="155" cy="106.7" r=".38"/>
<circle cx="144.8" cy="109.2" r=".38"/>
<circle cx="144.8" cy="111.8" r=".38"/>
<circle cx="158.8" cy="119.4" r=".38"/>
<circle cx="158.8" cy="121.9" r=".38"/>
<circle cx="158.8" cy="124.5" r=".38"/>
<circle cx="152.5" cy="114.3" r=".38"/>
<circle cx="152.5" cy="116.8" r=".38"/>
<circle cx="153.7" cy="115.6" r=".38"/>
<circle cx="153.7" cy="124.5" r=".38"/>
<circle cx="155" cy="121.9" r=".38"/>
<circle cx="140.5" cy="83.1" r=".38"/>
<circle cx="153.2" cy="88.6" r=".38"/>
<circle cx="145.6" cy="83.1" r=".38"/>
<circle cx="135.4" cy="88.6" r=".38"/>
<circle cx="137.2" cy="124.5" r=".38"/>
<circle cx="135.9" cy="124.5" r=".38"/>
<circle cx="135.9" cy="125.7" r=".38"/>
<circle cx="137.2" cy="125.7" r=".38"/>
<circle cx="142.3" cy="128.3" r=".38"/>
<circle cx="149.2" cy="128.3" r=".38"/>
</g>
<g fill="#fff">
<path d="M105.4 125.5h.2l.1 .2-.1 .2h-.2l-.1-.2z"/>
<path d="M106.6 125.5h.2l.1 .2-.1 .2h-.2l-.1-.2z"/>
<path d="M107.9 125.5h.2l.1 .2-.1 .2h-.2l-.1-.2z"/>
<path d="M107.9 126.8h.2l.1 .2-.1 .2h-.2l-.1-.2z"/>
<path d="M106.6 126.8h.2l.1 .2-.1 .2h-.2l-.1-.2z"/>
<path d="M105.4 126.8h.2l.1 .2-.1 .2h-.2l-.1-.2z"/>
<path d="M105.4 128.1h.2l.1 .2-.1 .2h-.2l-.1-.2z"/>
<path d="M106.6 128.1h.2l.1 .2-.1 .2h-.2l-.1-.2z"/>
<path d="M107.9 128.1h.2l.1 .2-.1 .2h-.2l-.1-.2z"/>
<path d="M138.4 105.2h.2l.1 .2-.1 .2h-.2l-.1-.2z"/>
<path d="M135.8 105.2h.2l.2 .2-.2 .2h-.2l-.1-.2z"/>
<path d="M135.8 102.7h.2l.2 .2-.2 .2h-.2l-.1-.2z"/>
<path d="M135.8 107.4h.2l.2 .2-.2 .2h-.2l-.1-.2z"/>
<path d="M132 95.1h.2l.1 .1-.1 .2h-.2l-.1-.2z"/>
<path d="M133.3 101.4h.2l.1 .2-.1 .2h-.2l-.1-.2z"/>
<path d="M133.3 92.5h.2l.1 .2-.1 .2h-.2l-.1-.2z"/>
<path d="M120.1 82.9h.2l.1 .2-.1 .1h-.2l-.1-.1z"/>
<path d="M127.7 82.9h.2l.1 .2-.1 .1h-.2l-.1-.1z"/>
<path d="M125.2 88.4h.2l.1 .2-.1 .1h-.2l-.1-.1z"/>
<path d="M126.3 88.9h.2l.1 .2-.1 .2h-.2l-.1-.2z"/>
<path d="M109.9 82.9h.2l.2 .2-.2 .1h-.2l-.1-.1z"/>
<path d="M115 88.4h.2l.1 .2-.1 .1h-.2l-.1-.1z"/>
<path d="M104.9 88.4h.2l.1 .2-.1 .1h-.2l-.2-.1z"/>
<path d="M113.7 88.7h.2l.1 .2-.1 .2h-.2l-.1-.2z"/>
<path d="M111.2 89.1h.2l.1 .2-.1 .2h-.2l-.1-.2z"/>
<path d="M125.7 124.3h.2l.1 .2-.1 .1h-.2l-.1-.1z"/>
<path d="M120.6 124.3h.2l.1 .2-.1 .1h-.2l-.1-.1z"/>
<path d="M123.7 125.5h.2l.2 .2-.2 .2h-.2l-.1-.2z"/>
<path d="M121.2 125.5h.2l.1 .2-.1 .2h-.2l-.1-.2z"/>
<path d="M140.9 102.7h.2l.1 .2-.1 .2h-.2l-.1-.2z"/>
<path d="M138.4 102.7h.2l.1 .2-.1 .2h-.2l-.1-.2z"/>
<path d="M138.4 100.5h.2l.1 .2-.1 .2h-.2l-.1-.2z"/>
<path d="M140.9 100.5h.2l.1 .2-.1 .2h-.2l-.1-.2z"/>
<path d="M135.8 100.5h.2l.2 .2-.2 .2h-.2l-.1-.2z"/>
<path d="M138.4 93.8h.2l.1 .2-.1 .2h-.2l-.1-.2z"/>
<path d="M144.7 95.1h.2l.1 .1-.1 .2h-.2l-.1-.2z"/>
<path d="M140.9 105.2h.2l.1 .2-.1 .2h-.2l-.1-.2z"/>
<path d="M143.5 102.7h.2l.1 .2-.1 .2h-.2l-.1-.2z"/>
<path d="M140.9 107.4h.2l.1 .2-.1 .2h-.2l-.1-.2z"/>
<path d="M138.4 107.4h.2l.1 .2-.1 .2h-.2l-.1-.2z"/>
<path d="M143.5 100.5h.2l.1 .2-.1 .2h-.2l-.1-.2z"/>
<path d="M143.5 105.2h.2l.1 .2-.1 .2h-.2l-.1-.2z"/>
<path d="M143.5 107.4h.2l.1 .2-.1 .2h-.2l-.1-.2z"/>
<path d="M152.4 106.5h.2l.1 .2-.1 .2h-.2l-.2-.2z"/>
<path d="M152.4 109h.2l.1 .2-.1 .2h-.2l-.2-.2z"/>
<path d="M152.4 111.6h.2l.1 .2-.1 .1h-.2l-.2-.1z"/>
<path d="M154.9 106.5h.2l.1 .2-.1 .2h-.2l-.1-.2z"/>
<path d="M144.7 109h.2l.1 .2-.1 .2h-.2l-.1-.2z"/>
<path d="M144.7 111.6h.2l.1 .2-.1 .1h-.2l-.1-.1z"/>
<path d="M158.7 119.2h.2l.1 .2-.1 .2h-.2l-.1-.2z"/>
<path d="M158.7 121.7h.2l.1 .2-.1 .2h-.2l-.1-.2z"/>
<path d="M158.7 124.3h.2l.1 .2-.1 .1h-.2l-.1-.1z"/>
<path d="M152.4 114.1h.2l.1 .2-.1 .2h-.2l-.2-.2z"/>
<path d="M152.4 116.7h.2l.1 .1-.1 .2h-.2l-.2-.2z"/>
<path d="M153.6 115.4h.2l.1 .2-.1 .2h-.2l-.1-.2z"/>
<path d="M153.6 124.3h.2l.1 .2-.1 .1h-.2l-.1-.1z"/>
<path d="M154.9 121.7h.2l.1 .2-.1 .2h-.2l-.1-.2z"/>
<path d="M140.4 82.9h.2l.1 .2-.1 .1h-.2l-.1-.1z"/>
<path d="M153.1 88.4h.2l.1 .2-.1 .1h-.2l-.1-.1z"/>
<path d="M145.5 82.9h.2l.1 .2-.1 .1h-.2l-.1-.1z"/>
<path d="M135.3 88.4h.2l.2 .2-.2 .1h-.2l-.1-.1z"/>
<path d="M137.1 124.3h.2l.1 .2-.1 .1h-.2l-.1-.1z"/>
<path d="M135.8 124.3h.2l.2 .2-.2 .1h-.2l-.1-.1z"/>
<path d="M135.8 125.5h.2l.2 .2-.2 .2h-.2l-.1-.2z"/>
<path d="M137.1 125.5h.2l.1 .2-.1 .2h-.2l-.1-.2z"/>
<path d="M142.2 128.1h.2l.1 .2-.1 .2h-.2l-.1-.2z"/>
<path d="M149.1 128.1h.2l.2 .2-.2 .2h-.2l-.1-.2z"/>
<circle cx="137.2" cy="118.1" r=".55"/>
<circle cx="139.8" cy="118.1" r=".55"/>
<circle cx="158" cy="135" r="1.4"/>
<circle cx="153.2" cy="87.2" r=".55"/>
<circle cx="142.3" cy="134.6" r=".55"/>
<circle cx="144.8" cy="134.6" r=".55"/>
<circle cx="151.8" cy="134.6" r=".55"/>
<circle cx="149.2" cy="134.6" r=".55"/>
<circle cx="151.9" cy="85.9" r=".97"/>
<circle cx="138" cy="87.2" r=".55"/>
<circle cx="140.5" cy="87.2" r=".55"/>
<circle cx="143.1" cy="87.2" r=".55"/>
<circle cx="145.6" cy="87.2" r=".55"/>
<circle cx="148.1" cy="87.2" r=".55"/>
<circle cx="150.7" cy="87.2" r=".55"/>
<circle cx="130.4" cy="87.2" r=".55"/>
<circle cx="132.9" cy="87.2" r=".55"/>
<circle cx="135.4" cy="87.2" r=".55"/>
<circle cx="130.4" cy="84.7" r=".55"/>
<circle cx="132.9" cy="84.7" r=".55"/>
<circle cx="135.4" cy="84.7" r=".55"/>
<circle cx="158" cy="85.9" r="1.4"/>
<circle cx="138" cy="84.7" r=".55"/>
<circle cx="140.5" cy="84.7" r=".55"/>
<circle cx="143.1" cy="84.7" r=".55"/>
<circle cx="145.6" cy="84.7" r=".55"/>
<circle cx="148.1" cy="84.7" r=".55"/>
<circle cx="150.7" cy="84.7" r=".55"/>
<circle cx="153.2" cy="84.7" r=".55"/>
<circle cx="125.4" cy="114" r="1.57"/>
<circle cx="105.5" cy="114" r="1.57"/>
<circle cx="105.5" cy="94" r="1.57"/>
<circle cx="100" cy="135" r="1.4"/>
<circle cx="112.6" cy="87.2" r=".55"/>
<circle cx="115.1" cy="87.2" r=".55"/>
<circle cx="117.7" cy="87.2" r=".55"/>
<circle cx="112.6" cy="84.7" r=".55"/>
<circle cx="115.1" cy="84.7" r=".55"/>
<circle cx="100" cy="85.9" r="1.4"/>
<circle cx="106.2" cy="85.9" r=".97"/>
<circle cx="105" cy="87.2" r=".55"/>
<circle cx="107.5" cy="87.2" r=".55"/>
<circle cx="110" cy="87.2" r=".55"/>
<circle cx="105" cy="84.7" r=".55"/>
<circle cx="107.5" cy="84.7" r=".55"/>
<circle cx="110" cy="84.7" r=".55"/>
<circle cx="125.4" cy="94" r="1.57"/>
<circle cx="122.7" cy="87.2" r=".55"/>
<circle cx="125.3" cy="87.2" r=".55"/>
<circle cx="127.8" cy="87.2" r=".55"/>
<circle cx="120.2" cy="87.2" r=".55"/>
<circle cx="117.7" cy="84.7" r=".55"/>
<circle cx="120.2" cy="84.7" r=".55"/>
<circle cx="122.7" cy="84.7" r=".55"/>
<circle cx="125.3" cy="84.7" r=".55"/>
<circle cx="127.8" cy="84.7" r=".55"/>
<circle cx="137.2" cy="115.6" r=".55"/>
<circle cx="130.9" cy="114.3" r=".47"/>
<circle cx="133.4" cy="116.8" r=".47"/>
<circle cx="130.9" cy="119.4" r=".47"/>
<circle cx="142.3" cy="132.1" r=".55"/>
<circle cx="144.8" cy="132.1" r=".55"/>
<circle cx="151.8" cy="132.1" r=".55"/>
<circle cx="149.2" cy="132.1" r=".55"/>
<circle cx="139.8" cy="115.6" r=".55"/>
<circle cx="156.8" cy="93.3" r=".55"/>
<circle cx="156.8" cy="90.8" r=".55"/>
<circle cx="159.3" cy="93.3" r=".55"/>
<circle cx="159.3" cy="90.8" r=".55"/>
<circle cx="102.9" cy="121.9" r=".72"/>
<circle cx="102.9" cy="127" r=".72"/>
<circle cx="113.7" cy="132.1" r=".55"/>
<circle cx="116.2" cy="132.1" r=".55"/>
<circle cx="118.8" cy="132.1" r=".55"/>
<circle cx="121.3" cy="132.1" r=".55"/>
<circle cx="123.8" cy="132.1" r=".55"/>
</g>
</svg>
